# Autogenerated file; please don't edit
# date: 2024-05-13 13:33:05.137460

########################################################################
#
# Copyright 2024 IHP PDK Authors
# 
# Licensed under the Apache License, Version 2.0 (the "License");
# you may not use this file except in compliance with the License.
# You may obtain a copy of the License at
# 
#    https://www.apache.org/licenses/LICENSE-2.0
# 
# Unless required by applicable law or agreed to in writing, software
# distributed under the License is distributed on an "AS IS" BASIS,
# WITHOUT WARRANTIES OR CONDITIONS OF ANY KIND, either express or implied.
# See the License for the specific language governing permissions and
# limitations under the License.
#
########################################################################

VERSION 5.7 ;

SITE sg13g2_ioSite
    CLASS PAD ;
    SYMMETRY R90 ;
    SIZE 1.00 BY 180.00 ;
END sg13g2_ioSite

SITE sg13g2_cornerSite
    CLASS PAD ;
    SYMMETRY R90 ;
    SIZE 180.00 BY 180.00 ;
END sg13g2_cornerSite

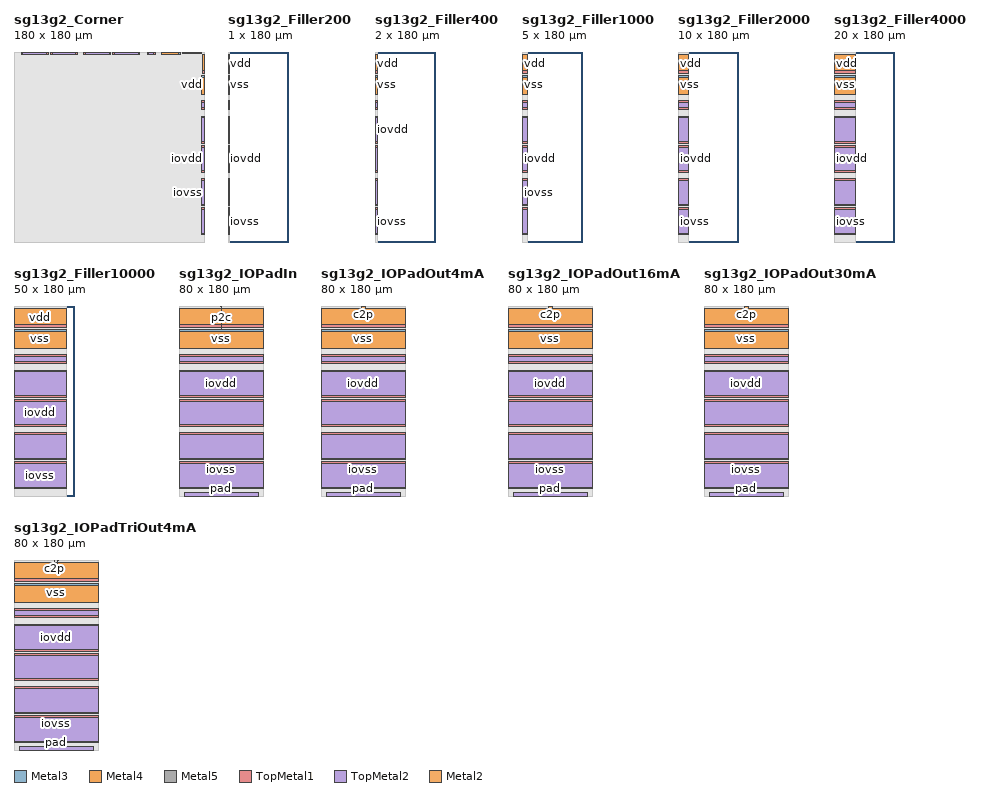
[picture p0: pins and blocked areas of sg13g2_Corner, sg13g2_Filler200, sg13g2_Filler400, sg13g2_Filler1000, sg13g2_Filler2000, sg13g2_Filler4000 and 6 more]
MACRO sg13g2_Corner
    CLASS PAD SPACER ;
    ORIGIN 0.000 0.000 ;
    FOREIGN sg13g2_Corner 0.000 0.000 ;
    SIZE 180.000 BY 180.000 ;
    SYMMETRY X Y R90 ;
    SITE sg13g2_cornerSite ;
  PIN iovdd
    DIRECTION INOUT ;
    USE POWER ;
    PORT
      LAYER Metal3 ;
        RECT 178.000 66.000 180.000 91.500 ;
    END
    PORT
      LAYER Metal3 ;
        RECT 93.500 178.000 119.000 180.000 ;
    END
    PORT
      LAYER Metal3 ;
        RECT 66.000 178.000 91.500 180.000 ;
    END
    PORT
      LAYER Metal3 ;
        RECT 178.000 93.500 180.000 119.000 ;
    END
    PORT
      LAYER Metal4 ;
        RECT 178.000 66.000 180.000 91.500 ;
    END
    PORT
      LAYER Metal4 ;
        RECT 93.500 178.000 119.000 180.000 ;
    END
    PORT
      LAYER Metal4 ;
        RECT 66.000 178.000 91.500 180.000 ;
    END
    PORT
      LAYER Metal4 ;
        RECT 178.000 93.500 180.000 119.000 ;
    END
    PORT
      LAYER Metal5 ;
        RECT 178.000 66.000 180.000 91.500 ;
    END
    PORT
      LAYER Metal5 ;
        RECT 93.500 178.000 119.000 180.000 ;
    END
    PORT
      LAYER Metal5 ;
        RECT 66.000 178.000 91.500 180.000 ;
    END
    PORT
      LAYER Metal5 ;
        RECT 178.000 93.500 180.000 119.000 ;
    END
    PORT
      LAYER TopMetal1 ;
        RECT 178.000 66.000 180.000 91.500 ;
    END
    PORT
      LAYER TopMetal1 ;
        RECT 93.500 178.000 119.000 180.000 ;
    END
    PORT
      LAYER TopMetal1 ;
        RECT 66.000 178.000 91.500 180.000 ;
    END
    PORT
      LAYER TopMetal1 ;
        RECT 178.000 93.500 180.000 119.000 ;
    END
    PORT
      LAYER TopMetal2 ;
        RECT 67.500 178.000 90.000 180.000 ;
    END
    PORT
      LAYER TopMetal2 ;
        RECT 178.000 67.500 180.000 90.000 ;
    END
    PORT
      LAYER TopMetal2 ;
        RECT 95.000 178.000 117.500 180.000 ;
    END
    PORT
      LAYER TopMetal2 ;
        RECT 178.000 95.000 180.000 117.500 ;
    END
  END iovdd
  PIN iovss
    DIRECTION INOUT ;
    USE GROUND ;
    PORT
      LAYER Metal3 ;
        RECT 178.000 34.500 180.000 60.000 ;
    END
    PORT
      LAYER Metal3 ;
        RECT 7.000 178.000 32.500 180.000 ;
    END
    PORT
      LAYER Metal3 ;
        RECT 178.000 126.000 180.000 134.000 ;
    END
    PORT
      LAYER Metal3 ;
        RECT 126.000 178.000 134.000 180.000 ;
    END
    PORT
      LAYER Metal3 ;
        RECT 34.500 178.000 60.000 180.000 ;
    END
    PORT
      LAYER Metal3 ;
        RECT 178.000 7.000 180.000 32.500 ;
    END
    PORT
      LAYER Metal4 ;
        RECT 178.000 34.500 180.000 60.000 ;
    END
    PORT
      LAYER Metal4 ;
        RECT 7.000 178.000 32.500 180.000 ;
    END
    PORT
      LAYER Metal4 ;
        RECT 178.000 126.000 180.000 134.000 ;
    END
    PORT
      LAYER Metal4 ;
        RECT 126.000 178.000 134.000 180.000 ;
    END
    PORT
      LAYER Metal4 ;
        RECT 34.500 178.000 60.000 180.000 ;
    END
    PORT
      LAYER Metal4 ;
        RECT 178.000 7.000 180.000 32.500 ;
    END
    PORT
      LAYER Metal5 ;
        RECT 178.000 34.500 180.000 60.000 ;
    END
    PORT
      LAYER Metal5 ;
        RECT 7.000 178.000 32.500 180.000 ;
    END
    PORT
      LAYER Metal5 ;
        RECT 178.000 126.000 180.000 134.000 ;
    END
    PORT
      LAYER Metal5 ;
        RECT 126.000 178.000 134.000 180.000 ;
    END
    PORT
      LAYER Metal5 ;
        RECT 34.500 178.000 60.000 180.000 ;
    END
    PORT
      LAYER Metal5 ;
        RECT 178.000 7.000 180.000 32.500 ;
    END
    PORT
      LAYER TopMetal1 ;
        RECT 178.000 34.500 180.000 60.000 ;
    END
    PORT
      LAYER TopMetal1 ;
        RECT 7.000 178.000 32.500 180.000 ;
    END
    PORT
      LAYER TopMetal1 ;
        RECT 178.000 126.000 180.000 134.000 ;
    END
    PORT
      LAYER TopMetal1 ;
        RECT 126.000 178.000 134.000 180.000 ;
    END
    PORT
      LAYER TopMetal1 ;
        RECT 34.500 178.000 60.000 180.000 ;
    END
    PORT
      LAYER TopMetal1 ;
        RECT 178.000 7.000 180.000 32.500 ;
    END
    PORT
      LAYER TopMetal2 ;
        RECT 178.000 127.500 180.000 132.500 ;
    END
    PORT
      LAYER TopMetal2 ;
        RECT 178.000 36.000 180.000 58.500 ;
    END
    PORT
      LAYER TopMetal2 ;
        RECT 8.500 178.000 31.000 180.000 ;
    END
    PORT
      LAYER TopMetal2 ;
        RECT 178.000 8.500 180.000 31.000 ;
    END
    PORT
      LAYER TopMetal2 ;
        RECT 36.000 178.000 58.500 180.000 ;
    END
    PORT
      LAYER TopMetal2 ;
        RECT 127.500 178.000 132.500 180.000 ;
    END
  END iovss
  PIN vdd
    DIRECTION INOUT ;
    USE POWER ;
    PORT
      LAYER Metal3 ;
        RECT 160.000 178.590 178.000 180.000 ;
    END
    PORT
      LAYER Metal3 ;
        RECT 178.590 160.000 180.000 178.000 ;
    END
    PORT
      LAYER Metal4 ;
        RECT 178.000 140.000 180.000 155.800 ;
    END
    PORT
      LAYER Metal4 ;
        RECT 140.000 178.000 155.800 180.000 ;
    END
    PORT
      LAYER Metal5 ;
        RECT 178.000 140.000 180.000 158.000 ;
    END
    PORT
      LAYER Metal5 ;
        RECT 140.000 178.000 158.000 180.000 ;
    END
    PORT
      LAYER TopMetal1 ;
        RECT 178.000 140.000 180.000 158.000 ;
    END
    PORT
      LAYER TopMetal1 ;
        RECT 140.000 178.000 158.000 180.000 ;
    END
  END vdd
  PIN vss
    DIRECTION INOUT ;
    USE GROUND ;
    PORT
      LAYER Metal3 ;
        RECT 178.000 140.000 180.000 158.000 ;
    END
    PORT
      LAYER Metal3 ;
        RECT 140.000 178.000 158.000 180.000 ;
    END
    PORT
      LAYER Metal4 ;
        RECT 178.590 162.200 180.000 178.000 ;
    END
    PORT
      LAYER Metal4 ;
        RECT 162.200 178.590 178.000 180.000 ;
    END
    PORT
      LAYER Metal5 ;
        RECT 160.000 178.590 178.000 180.000 ;
    END
    PORT
      LAYER Metal5 ;
        RECT 178.590 160.000 180.000 178.000 ;
    END
    PORT
      LAYER TopMetal1 ;
        RECT 160.000 178.590 178.000 180.000 ;
    END
    PORT
      LAYER TopMetal1 ;
        RECT 178.590 160.000 180.000 178.000 ;
    END
  END vss
  OBS
    LAYER Metal1 ;
      RECT 0.000 0.000 180.000 180.000 ;
    LAYER Metal2 ;
      RECT 0.000 0.000 180.000 180.000 ;
    LAYER Metal3 ;
      RECT 0.000 0.000 180.000 180.000 ;
    LAYER Metal4 ;
      RECT 0.000 0.000 180.000 180.000 ;
    LAYER Metal5 ;
      RECT 0.000 0.000 180.000 180.000 ;
    LAYER TopMetal1 ;
      RECT 0.000 0.000 180.000 180.000 ;
    LAYER TopMetal2 ;
      RECT 0.000 0.000 180.000 180.000 ;
    LAYER Via1 ;
      RECT 0.000 0.000 180.000 180.000 ;
    LAYER Via2 ;
      RECT 0.000 0.000 180.000 180.000 ;
  END
END sg13g2_Corner

MACRO sg13g2_Filler200
    CLASS PAD SPACER ;
    ORIGIN 0.000 0.000 ;
    FOREIGN sg13g2_Filler200 0.000 0.000 ;
    SIZE 1.000 BY 180.000 ;
    SYMMETRY X Y R90 ;
    SITE sg13g2_ioSite ;
  PIN iovdd
    DIRECTION INOUT ;
    USE POWER ;
    PORT
      LAYER Metal3 ;
        RECT 0.000 66.000 1.000 91.500 ;
    END
    PORT
      LAYER Metal3 ;
        RECT 0.000 93.500 1.000 119.000 ;
    END
    PORT
      LAYER Metal4 ;
        RECT 0.000 66.000 1.000 91.500 ;
    END
    PORT
      LAYER Metal4 ;
        RECT 0.000 93.500 1.000 119.000 ;
    END
    PORT
      LAYER Metal5 ;
        RECT 0.000 66.000 1.000 91.500 ;
    END
    PORT
      LAYER Metal5 ;
        RECT 0.000 93.500 1.000 119.000 ;
    END
    PORT
      LAYER TopMetal1 ;
        RECT 0.000 66.000 1.000 91.500 ;
    END
    PORT
      LAYER TopMetal1 ;
        RECT 0.000 93.500 1.000 119.000 ;
    END
    PORT
      LAYER TopMetal2 ;
        RECT 0.000 95.000 1.000 117.500 ;
    END
    PORT
      LAYER TopMetal2 ;
        RECT 0.000 67.500 1.000 90.000 ;
    END
  END iovdd
  PIN iovss
    DIRECTION INOUT ;
    USE GROUND ;
    PORT
      LAYER Metal3 ;
        RECT 0.000 7.000 1.000 32.500 ;
    END
    PORT
      LAYER Metal3 ;
        RECT 0.000 126.000 1.000 134.000 ;
    END
    PORT
      LAYER Metal3 ;
        RECT 0.000 34.500 1.000 60.000 ;
    END
    PORT
      LAYER Metal4 ;
        RECT 0.000 7.000 1.000 32.500 ;
    END
    PORT
      LAYER Metal4 ;
        RECT 0.000 126.000 1.000 134.000 ;
    END
    PORT
      LAYER Metal4 ;
        RECT 0.000 34.500 1.000 60.000 ;
    END
    PORT
      LAYER Metal5 ;
        RECT 0.000 7.000 1.000 32.500 ;
    END
    PORT
      LAYER Metal5 ;
        RECT 0.000 126.000 1.000 134.000 ;
    END
    PORT
      LAYER Metal5 ;
        RECT 0.000 34.500 1.000 60.000 ;
    END
    PORT
      LAYER TopMetal1 ;
        RECT 0.000 7.000 1.000 32.500 ;
    END
    PORT
      LAYER TopMetal1 ;
        RECT 0.000 126.000 1.000 134.000 ;
    END
    PORT
      LAYER TopMetal1 ;
        RECT 0.000 34.500 1.000 60.000 ;
    END
    PORT
      LAYER TopMetal2 ;
        RECT 0.000 8.500 1.000 31.000 ;
    END
    PORT
      LAYER TopMetal2 ;
        RECT 0.000 127.500 1.000 132.500 ;
    END
    PORT
      LAYER TopMetal2 ;
        RECT 0.000 36.000 1.000 58.500 ;
    END
  END iovss
  PIN vdd
    DIRECTION INOUT ;
    USE POWER ;
    PORT
      LAYER Metal3 ;
        RECT 0.000 160.000 1.000 178.000 ;
    END
    PORT
      LAYER Metal4 ;
        RECT 0.000 140.000 1.000 155.800 ;
    END
    PORT
      LAYER Metal5 ;
        RECT 0.000 140.000 1.000 158.000 ;
    END
    PORT
      LAYER TopMetal1 ;
        RECT 0.000 140.000 1.000 158.000 ;
    END
  END vdd
  PIN vss
    DIRECTION INOUT ;
    USE GROUND ;
    PORT
      LAYER Metal3 ;
        RECT 0.000 140.000 1.000 158.000 ;
    END
    PORT
      LAYER Metal4 ;
        RECT 0.000 162.200 1.000 178.000 ;
    END
    PORT
      LAYER Metal5 ;
        RECT 0.000 160.000 1.000 178.000 ;
    END
    PORT
      LAYER TopMetal1 ;
        RECT 0.000 160.000 1.000 178.000 ;
    END
  END vss
  OBS
    LAYER Metal1 ;
      RECT 0.000 0.000 1.000 180.000 ;
    LAYER Metal2 ;
      RECT 0.000 0.000 1.000 180.000 ;
    LAYER Metal3 ;
      RECT 0.000 0.000 1.000 178.000 ;
    LAYER Metal4 ;
      RECT 0.000 0.000 1.000 178.000 ;
    LAYER Metal5 ;
      RECT 0.000 0.000 1.000 178.000 ;
    LAYER TopMetal1 ;
      RECT 0.000 0.000 1.000 178.000 ;
    LAYER TopMetal2 ;
      RECT 0.000 8.500 1.000 132.500 ;
    LAYER Via1 ;
      RECT 0.000 0.000 1.000 180.000 ;
    LAYER Via2 ;
      RECT 0.000 0.000 1.000 180.000 ;
  END
END sg13g2_Filler200

MACRO sg13g2_Filler400
    CLASS PAD SPACER ;
    ORIGIN 0.000 0.000 ;
    FOREIGN sg13g2_Filler400 0.000 0.000 ;
    SIZE 2.000 BY 180.000 ;
    SYMMETRY X Y R90 ;
    SITE sg13g2_ioSite ;
  PIN iovdd
    DIRECTION INOUT ;
    USE POWER ;
    PORT
      LAYER Metal3 ;
        RECT 0.000 93.500 2.000 119.000 ;
    END
    PORT
      LAYER Metal3 ;
        RECT 0.000 66.000 2.000 91.500 ;
    END
    PORT
      LAYER Metal4 ;
        RECT 0.000 93.500 2.000 119.000 ;
    END
    PORT
      LAYER Metal4 ;
        RECT 0.000 66.000 2.000 91.500 ;
    END
    PORT
      LAYER Metal5 ;
        RECT 0.000 93.500 2.000 119.000 ;
    END
    PORT
      LAYER Metal5 ;
        RECT 0.000 66.000 2.000 91.500 ;
    END
    PORT
      LAYER TopMetal1 ;
        RECT 0.000 93.500 2.000 119.000 ;
    END
    PORT
      LAYER TopMetal1 ;
        RECT 0.000 66.000 2.000 91.500 ;
    END
    PORT
      LAYER TopMetal2 ;
        RECT 0.000 67.500 2.000 90.000 ;
    END
    PORT
      LAYER TopMetal2 ;
        RECT 0.000 95.000 2.000 117.500 ;
    END
  END iovdd
  PIN iovss
    DIRECTION INOUT ;
    USE GROUND ;
    PORT
      LAYER Metal3 ;
        RECT 0.000 126.000 2.000 134.000 ;
    END
    PORT
      LAYER Metal3 ;
        RECT 0.000 7.000 2.000 32.500 ;
    END
    PORT
      LAYER Metal3 ;
        RECT 0.000 34.500 2.000 60.000 ;
    END
    PORT
      LAYER Metal4 ;
        RECT 0.000 126.000 2.000 134.000 ;
    END
    PORT
      LAYER Metal4 ;
        RECT 0.000 7.000 2.000 32.500 ;
    END
    PORT
      LAYER Metal4 ;
        RECT 0.000 34.500 2.000 60.000 ;
    END
    PORT
      LAYER Metal5 ;
        RECT 0.000 126.000 2.000 134.000 ;
    END
    PORT
      LAYER Metal5 ;
        RECT 0.000 7.000 2.000 32.500 ;
    END
    PORT
      LAYER Metal5 ;
        RECT 0.000 34.500 2.000 60.000 ;
    END
    PORT
      LAYER TopMetal1 ;
        RECT 0.000 126.000 2.000 134.000 ;
    END
    PORT
      LAYER TopMetal1 ;
        RECT 0.000 7.000 2.000 32.500 ;
    END
    PORT
      LAYER TopMetal1 ;
        RECT 0.000 34.500 2.000 60.000 ;
    END
    PORT
      LAYER TopMetal2 ;
        RECT 0.000 8.500 2.000 31.000 ;
    END
    PORT
      LAYER TopMetal2 ;
        RECT 0.000 36.000 2.000 58.500 ;
    END
    PORT
      LAYER TopMetal2 ;
        RECT 0.000 127.500 2.000 132.500 ;
    END
  END iovss
  PIN vdd
    DIRECTION INOUT ;
    USE POWER ;
    PORT
      LAYER Metal3 ;
        RECT 0.000 160.000 2.000 178.000 ;
    END
    PORT
      LAYER Metal4 ;
        RECT 0.000 140.000 2.000 155.800 ;
    END
    PORT
      LAYER Metal5 ;
        RECT 0.000 140.000 2.000 158.000 ;
    END
    PORT
      LAYER TopMetal1 ;
        RECT 0.000 140.000 2.000 158.000 ;
    END
  END vdd
  PIN vss
    DIRECTION INOUT ;
    USE GROUND ;
    PORT
      LAYER Metal3 ;
        RECT 0.000 140.000 2.000 158.000 ;
    END
    PORT
      LAYER Metal4 ;
        RECT 0.000 162.200 2.000 178.000 ;
    END
    PORT
      LAYER Metal5 ;
        RECT 0.000 160.000 2.000 178.000 ;
    END
    PORT
      LAYER TopMetal1 ;
        RECT 0.000 160.000 2.000 178.000 ;
    END
  END vss
  OBS
    LAYER Metal1 ;
      RECT 0.000 0.000 2.000 180.000 ;
    LAYER Metal2 ;
      RECT 0.000 0.000 2.000 180.000 ;
    LAYER Metal3 ;
      RECT 0.000 0.000 2.000 178.000 ;
    LAYER Metal4 ;
      RECT 0.000 0.000 2.000 178.000 ;
    LAYER Metal5 ;
      RECT 0.000 0.000 2.000 178.000 ;
    LAYER TopMetal1 ;
      RECT 0.000 0.000 2.000 178.000 ;
    LAYER TopMetal2 ;
      RECT 0.000 8.500 2.000 132.500 ;
    LAYER Via1 ;
      RECT 0.000 0.000 2.000 180.000 ;
    LAYER Via2 ;
      RECT 0.000 0.000 2.000 180.000 ;
  END
END sg13g2_Filler400

MACRO sg13g2_Filler1000
    CLASS PAD SPACER ;
    ORIGIN 0.000 0.000 ;
    FOREIGN sg13g2_Filler1000 0.000 0.000 ;
    SIZE 5.000 BY 180.000 ;
    SYMMETRY X Y R90 ;
    SITE sg13g2_ioSite ;
  PIN iovdd
    DIRECTION INOUT ;
    USE POWER ;
    PORT
      LAYER Metal3 ;
        RECT 0.000 66.000 5.000 91.500 ;
    END
    PORT
      LAYER Metal3 ;
        RECT 0.000 93.500 5.000 119.000 ;
    END
    PORT
      LAYER Metal4 ;
        RECT 0.000 66.000 5.000 91.500 ;
    END
    PORT
      LAYER Metal4 ;
        RECT 0.000 93.500 5.000 119.000 ;
    END
    PORT
      LAYER Metal5 ;
        RECT 0.000 66.000 5.000 91.500 ;
    END
    PORT
      LAYER Metal5 ;
        RECT 0.000 93.500 5.000 119.000 ;
    END
    PORT
      LAYER TopMetal1 ;
        RECT 0.000 66.000 5.000 91.500 ;
    END
    PORT
      LAYER TopMetal1 ;
        RECT 0.000 93.500 5.000 119.000 ;
    END
    PORT
      LAYER TopMetal2 ;
        RECT 0.000 95.000 5.000 117.500 ;
    END
    PORT
      LAYER TopMetal2 ;
        RECT 0.000 67.500 5.000 90.000 ;
    END
  END iovdd
  PIN iovss
    DIRECTION INOUT ;
    USE GROUND ;
    PORT
      LAYER Metal3 ;
        RECT 0.000 34.500 5.000 60.000 ;
    END
    PORT
      LAYER Metal3 ;
        RECT 0.000 7.000 5.000 32.500 ;
    END
    PORT
      LAYER Metal3 ;
        RECT 0.000 126.000 5.000 134.000 ;
    END
    PORT
      LAYER Metal4 ;
        RECT 0.000 34.500 5.000 60.000 ;
    END
    PORT
      LAYER Metal4 ;
        RECT 0.000 7.000 5.000 32.500 ;
    END
    PORT
      LAYER Metal4 ;
        RECT 0.000 126.000 5.000 134.000 ;
    END
    PORT
      LAYER Metal5 ;
        RECT 0.000 34.500 5.000 60.000 ;
    END
    PORT
      LAYER Metal5 ;
        RECT 0.000 7.000 5.000 32.500 ;
    END
    PORT
      LAYER Metal5 ;
        RECT 0.000 126.000 5.000 134.000 ;
    END
    PORT
      LAYER TopMetal1 ;
        RECT 0.000 34.500 5.000 60.000 ;
    END
    PORT
      LAYER TopMetal1 ;
        RECT 0.000 7.000 5.000 32.500 ;
    END
    PORT
      LAYER TopMetal1 ;
        RECT 0.000 126.000 5.000 134.000 ;
    END
    PORT
      LAYER TopMetal2 ;
        RECT 0.000 127.500 5.000 132.500 ;
    END
    PORT
      LAYER TopMetal2 ;
        RECT 0.000 36.000 5.000 58.500 ;
    END
    PORT
      LAYER TopMetal2 ;
        RECT 0.000 8.500 5.000 31.000 ;
    END
  END iovss
  PIN vdd
    DIRECTION INOUT ;
    USE POWER ;
    PORT
      LAYER Metal3 ;
        RECT 0.000 160.000 5.000 178.000 ;
    END
    PORT
      LAYER Metal4 ;
        RECT 0.000 140.000 5.000 155.800 ;
    END
    PORT
      LAYER Metal5 ;
        RECT 0.000 140.000 5.000 158.000 ;
    END
    PORT
      LAYER TopMetal1 ;
        RECT 0.000 140.000 5.000 158.000 ;
    END
  END vdd
  PIN vss
    DIRECTION INOUT ;
    USE GROUND ;
    PORT
      LAYER Metal3 ;
        RECT 0.000 140.000 5.000 158.000 ;
    END
    PORT
      LAYER Metal4 ;
        RECT 0.000 162.200 5.000 178.000 ;
    END
    PORT
      LAYER Metal5 ;
        RECT 0.000 160.000 5.000 178.000 ;
    END
    PORT
      LAYER TopMetal1 ;
        RECT 0.000 160.000 5.000 178.000 ;
    END
  END vss
  OBS
    LAYER Metal1 ;
      RECT 0.000 0.000 5.000 180.000 ;
    LAYER Metal2 ;
      RECT 0.000 0.000 5.000 180.000 ;
    LAYER Metal3 ;
      RECT 0.000 0.000 5.000 178.000 ;
    LAYER Metal4 ;
      RECT 0.000 0.000 5.000 178.000 ;
    LAYER Metal5 ;
      RECT 0.000 0.000 5.000 178.000 ;
    LAYER TopMetal1 ;
      RECT 0.000 0.000 5.000 178.000 ;
    LAYER TopMetal2 ;
      RECT 0.000 8.500 5.000 132.500 ;
    LAYER Via1 ;
      RECT 0.000 0.000 5.000 180.000 ;
    LAYER Via2 ;
      RECT 0.000 0.000 5.000 180.000 ;
  END
END sg13g2_Filler1000

MACRO sg13g2_Filler2000
    CLASS PAD SPACER ;
    ORIGIN 0.000 0.000 ;
    FOREIGN sg13g2_Filler2000 0.000 0.000 ;
    SIZE 10.000 BY 180.000 ;
    SYMMETRY X Y R90 ;
    SITE sg13g2_ioSite ;
  PIN iovdd
    DIRECTION INOUT ;
    USE POWER ;
    PORT
      LAYER Metal3 ;
        RECT 0.000 66.000 10.000 91.500 ;
    END
    PORT
      LAYER Metal3 ;
        RECT 0.000 93.500 10.000 119.000 ;
    END
    PORT
      LAYER Metal4 ;
        RECT 0.000 66.000 10.000 91.500 ;
    END
    PORT
      LAYER Metal4 ;
        RECT 0.000 93.500 10.000 119.000 ;
    END
    PORT
      LAYER Metal5 ;
        RECT 0.000 66.000 10.000 91.500 ;
    END
    PORT
      LAYER Metal5 ;
        RECT 0.000 93.500 10.000 119.000 ;
    END
    PORT
      LAYER TopMetal1 ;
        RECT 0.000 66.000 10.000 91.500 ;
    END
    PORT
      LAYER TopMetal1 ;
        RECT 0.000 93.500 10.000 119.000 ;
    END
    PORT
      LAYER TopMetal2 ;
        RECT 0.000 67.500 10.000 90.000 ;
    END
    PORT
      LAYER TopMetal2 ;
        RECT 0.000 95.000 10.000 117.500 ;
    END
  END iovdd
  PIN iovss
    DIRECTION INOUT ;
    USE GROUND ;
    PORT
      LAYER Metal3 ;
        RECT 0.000 126.000 10.000 134.000 ;
    END
    PORT
      LAYER Metal3 ;
        RECT 0.000 7.000 10.000 32.500 ;
    END
    PORT
      LAYER Metal3 ;
        RECT 0.000 34.500 10.000 60.000 ;
    END
    PORT
      LAYER Metal4 ;
        RECT 0.000 126.000 10.000 134.000 ;
    END
    PORT
      LAYER Metal4 ;
        RECT 0.000 7.000 10.000 32.500 ;
    END
    PORT
      LAYER Metal4 ;
        RECT 0.000 34.500 10.000 60.000 ;
    END
    PORT
      LAYER Metal5 ;
        RECT 0.000 126.000 10.000 134.000 ;
    END
    PORT
      LAYER Metal5 ;
        RECT 0.000 7.000 10.000 32.500 ;
    END
    PORT
      LAYER Metal5 ;
        RECT 0.000 34.500 10.000 60.000 ;
    END
    PORT
      LAYER TopMetal1 ;
        RECT 0.000 126.000 10.000 134.000 ;
    END
    PORT
      LAYER TopMetal1 ;
        RECT 0.000 7.000 10.000 32.500 ;
    END
    PORT
      LAYER TopMetal1 ;
        RECT 0.000 34.500 10.000 60.000 ;
    END
    PORT
      LAYER TopMetal2 ;
        RECT 0.000 8.500 10.000 31.000 ;
    END
    PORT
      LAYER TopMetal2 ;
        RECT 0.000 36.000 10.000 58.500 ;
    END
    PORT
      LAYER TopMetal2 ;
        RECT 0.000 127.500 10.000 132.500 ;
    END
  END iovss
  PIN vdd
    DIRECTION INOUT ;
    USE POWER ;
    PORT
      LAYER Metal3 ;
        RECT 0.000 160.000 10.000 178.000 ;
    END
    PORT
      LAYER Metal4 ;
        RECT 0.000 140.000 10.000 155.800 ;
    END
    PORT
      LAYER Metal5 ;
        RECT 0.000 140.000 10.000 158.000 ;
    END
    PORT
      LAYER TopMetal1 ;
        RECT 0.000 140.000 10.000 158.000 ;
    END
  END vdd
  PIN vss
    DIRECTION INOUT ;
    USE GROUND ;
    PORT
      LAYER Metal3 ;
        RECT 0.000 140.000 10.000 158.000 ;
    END
    PORT
      LAYER Metal4 ;
        RECT 0.000 162.200 10.000 178.000 ;
    END
    PORT
      LAYER Metal5 ;
        RECT 0.000 160.000 10.000 178.000 ;
    END
    PORT
      LAYER TopMetal1 ;
        RECT 0.000 160.000 10.000 178.000 ;
    END
  END vss
  OBS
    LAYER Metal1 ;
      RECT 0.000 0.000 10.000 180.000 ;
    LAYER Metal2 ;
      RECT 0.000 0.000 10.000 180.000 ;
    LAYER Metal3 ;
      RECT 0.000 0.000 10.000 178.000 ;
    LAYER Metal4 ;
      RECT 0.000 0.000 10.000 178.000 ;
    LAYER Metal5 ;
      RECT 0.000 0.000 10.000 178.000 ;
    LAYER TopMetal1 ;
      RECT 0.000 0.000 10.000 178.000 ;
    LAYER TopMetal2 ;
      RECT 0.000 8.500 10.000 132.500 ;
    LAYER Via1 ;
      RECT 0.000 0.000 10.000 180.000 ;
    LAYER Via2 ;
      RECT 0.000 0.000 10.000 180.000 ;
  END
END sg13g2_Filler2000

MACRO sg13g2_Filler4000
    CLASS PAD SPACER ;
    ORIGIN 0.000 0.000 ;
    FOREIGN sg13g2_Filler4000 0.000 0.000 ;
    SIZE 20.000 BY 180.000 ;
    SYMMETRY X Y R90 ;
    SITE sg13g2_ioSite ;
  PIN iovdd
    DIRECTION INOUT ;
    USE POWER ;
    PORT
      LAYER Metal3 ;
        RECT 0.000 66.000 20.000 91.500 ;
    END
    PORT
      LAYER Metal3 ;
        RECT 0.000 93.500 20.000 119.000 ;
    END
    PORT
      LAYER Metal4 ;
        RECT 0.000 66.000 20.000 91.500 ;
    END
    PORT
      LAYER Metal4 ;
        RECT 0.000 93.500 20.000 119.000 ;
    END
    PORT
      LAYER Metal5 ;
        RECT 0.000 66.000 20.000 91.500 ;
    END
    PORT
      LAYER Metal5 ;
        RECT 0.000 93.500 20.000 119.000 ;
    END
    PORT
      LAYER TopMetal1 ;
        RECT 0.000 66.000 20.000 91.500 ;
    END
    PORT
      LAYER TopMetal1 ;
        RECT 0.000 93.500 20.000 119.000 ;
    END
    PORT
      LAYER TopMetal2 ;
        RECT 0.000 95.000 20.000 117.500 ;
    END
    PORT
      LAYER TopMetal2 ;
        RECT 0.000 67.500 20.000 90.000 ;
    END
  END iovdd
  PIN iovss
    DIRECTION INOUT ;
    USE GROUND ;
    PORT
      LAYER Metal3 ;
        RECT 0.000 7.000 20.000 32.500 ;
    END
    PORT
      LAYER Metal3 ;
        RECT 0.000 34.500 20.000 60.000 ;
    END
    PORT
      LAYER Metal3 ;
        RECT 0.000 126.000 20.000 134.000 ;
    END
    PORT
      LAYER Metal4 ;
        RECT 0.000 7.000 20.000 32.500 ;
    END
    PORT
      LAYER Metal4 ;
        RECT 0.000 34.500 20.000 60.000 ;
    END
    PORT
      LAYER Metal4 ;
        RECT 0.000 126.000 20.000 134.000 ;
    END
    PORT
      LAYER Metal5 ;
        RECT 0.000 7.000 20.000 32.500 ;
    END
    PORT
      LAYER Metal5 ;
        RECT 0.000 34.500 20.000 60.000 ;
    END
    PORT
      LAYER Metal5 ;
        RECT 0.000 126.000 20.000 134.000 ;
    END
    PORT
      LAYER TopMetal1 ;
        RECT 0.000 7.000 20.000 32.500 ;
    END
    PORT
      LAYER TopMetal1 ;
        RECT 0.000 34.500 20.000 60.000 ;
    END
    PORT
      LAYER TopMetal1 ;
        RECT 0.000 126.000 20.000 134.000 ;
    END
    PORT
      LAYER TopMetal2 ;
        RECT 0.000 127.500 20.000 132.500 ;
    END
    PORT
      LAYER TopMetal2 ;
        RECT 0.000 36.000 20.000 58.500 ;
    END
    PORT
      LAYER TopMetal2 ;
        RECT 0.000 8.500 20.000 31.000 ;
    END
  END iovss
  PIN vdd
    DIRECTION INOUT ;
    USE POWER ;
    PORT
      LAYER Metal3 ;
        RECT 0.000 160.000 20.000 178.000 ;
    END
    PORT
      LAYER Metal4 ;
        RECT 0.000 140.000 20.000 155.800 ;
    END
    PORT
      LAYER Metal5 ;
        RECT 0.000 140.000 20.000 158.000 ;
    END
    PORT
      LAYER TopMetal1 ;
        RECT 0.000 140.000 20.000 158.000 ;
    END
  END vdd
  PIN vss
    DIRECTION INOUT ;
    USE GROUND ;
    PORT
      LAYER Metal3 ;
        RECT 0.000 140.000 20.000 158.000 ;
    END
    PORT
      LAYER Metal4 ;
        RECT 0.000 162.200 20.000 178.000 ;
    END
    PORT
      LAYER Metal5 ;
        RECT 0.000 160.000 20.000 178.000 ;
    END
    PORT
      LAYER TopMetal1 ;
        RECT 0.000 160.000 20.000 178.000 ;
    END
  END vss
  OBS
    LAYER Metal1 ;
      RECT 0.000 0.000 20.000 180.000 ;
    LAYER Metal2 ;
      RECT 0.000 0.000 20.000 180.000 ;
    LAYER Metal3 ;
      RECT 0.000 0.000 20.000 178.000 ;
    LAYER Metal4 ;
      RECT 0.000 0.000 20.000 178.000 ;
    LAYER Metal5 ;
      RECT 0.000 0.000 20.000 178.000 ;
    LAYER TopMetal1 ;
      RECT 0.000 0.000 20.000 178.000 ;
    LAYER TopMetal2 ;
      RECT 0.000 8.500 20.000 132.500 ;
    LAYER Via1 ;
      RECT 0.000 0.000 20.000 180.000 ;
    LAYER Via2 ;
      RECT 0.000 0.000 20.000 180.000 ;
  END
END sg13g2_Filler4000

MACRO sg13g2_Filler10000
    CLASS PAD SPACER ;
    ORIGIN 0.000 0.000 ;
    FOREIGN sg13g2_Filler10000 0.000 0.000 ;
    SIZE 50.000 BY 180.000 ;
    SYMMETRY X Y R90 ;
    SITE sg13g2_ioSite ;
  PIN iovdd
    DIRECTION INOUT ;
    USE POWER ;
    PORT
      LAYER Metal3 ;
        RECT 0.000 66.000 50.000 91.500 ;
    END
    PORT
      LAYER Metal3 ;
        RECT 0.000 93.500 50.000 119.000 ;
    END
    PORT
      LAYER Metal4 ;
        RECT 0.000 66.000 50.000 91.500 ;
    END
    PORT
      LAYER Metal4 ;
        RECT 0.000 93.500 50.000 119.000 ;
    END
    PORT
      LAYER Metal5 ;
        RECT 0.000 66.000 50.000 91.500 ;
    END
    PORT
      LAYER Metal5 ;
        RECT 0.000 93.500 50.000 119.000 ;
    END
    PORT
      LAYER TopMetal1 ;
        RECT 0.000 66.000 50.000 91.500 ;
    END
    PORT
      LAYER TopMetal1 ;
        RECT 0.000 93.500 50.000 119.000 ;
    END
    PORT
      LAYER TopMetal2 ;
        RECT 0.000 95.000 50.000 117.500 ;
    END
    PORT
      LAYER TopMetal2 ;
        RECT 0.000 67.500 50.000 90.000 ;
    END
  END iovdd
  PIN iovss
    DIRECTION INOUT ;
    USE GROUND ;
    PORT
      LAYER Metal3 ;
        RECT 0.000 7.000 50.000 32.500 ;
    END
    PORT
      LAYER Metal3 ;
        RECT 0.000 126.000 50.000 134.000 ;
    END
    PORT
      LAYER Metal3 ;
        RECT 0.000 34.500 50.000 60.000 ;
    END
    PORT
      LAYER Metal4 ;
        RECT 0.000 7.000 50.000 32.500 ;
    END
    PORT
      LAYER Metal4 ;
        RECT 0.000 126.000 50.000 134.000 ;
    END
    PORT
      LAYER Metal4 ;
        RECT 0.000 34.500 50.000 60.000 ;
    END
    PORT
      LAYER Metal5 ;
        RECT 0.000 7.000 50.000 32.500 ;
    END
    PORT
      LAYER Metal5 ;
        RECT 0.000 126.000 50.000 134.000 ;
    END
    PORT
      LAYER Metal5 ;
        RECT 0.000 34.500 50.000 60.000 ;
    END
    PORT
      LAYER TopMetal1 ;
        RECT 0.000 7.000 50.000 32.500 ;
    END
    PORT
      LAYER TopMetal1 ;
        RECT 0.000 126.000 50.000 134.000 ;
    END
    PORT
      LAYER TopMetal1 ;
        RECT 0.000 34.500 50.000 60.000 ;
    END
    PORT
      LAYER TopMetal2 ;
        RECT 0.000 8.500 50.000 31.000 ;
    END
    PORT
      LAYER TopMetal2 ;
        RECT 0.000 127.500 50.000 132.500 ;
    END
    PORT
      LAYER TopMetal2 ;
        RECT 0.000 36.000 50.000 58.500 ;
    END
  END iovss
  PIN vdd
    DIRECTION INOUT ;
    USE POWER ;
    PORT
      LAYER Metal3 ;
        RECT 0.000 160.000 50.000 178.000 ;
    END
    PORT
      LAYER Metal4 ;
        RECT 0.000 140.000 50.000 155.800 ;
    END
    PORT
      LAYER Metal5 ;
        RECT 0.000 140.000 50.000 158.000 ;
    END
    PORT
      LAYER TopMetal1 ;
        RECT 0.000 140.000 50.000 158.000 ;
    END
  END vdd
  PIN vss
    DIRECTION INOUT ;
    USE GROUND ;
    PORT
      LAYER Metal3 ;
        RECT 0.000 140.000 50.000 158.000 ;
    END
    PORT
      LAYER Metal4 ;
        RECT 0.000 162.200 50.000 178.000 ;
    END
    PORT
      LAYER Metal5 ;
        RECT 0.000 160.000 50.000 178.000 ;
    END
    PORT
      LAYER TopMetal1 ;
        RECT 0.000 160.000 50.000 178.000 ;
    END
  END vss
  OBS
    LAYER Metal1 ;
      RECT 0.000 0.000 50.000 180.000 ;
    LAYER Metal2 ;
      RECT 0.000 0.000 50.000 180.000 ;
    LAYER Metal3 ;
      RECT 0.000 0.000 50.000 178.000 ;
    LAYER Metal4 ;
      RECT 0.000 0.000 50.000 178.000 ;
    LAYER Metal5 ;
      RECT 0.000 0.000 50.000 178.000 ;
    LAYER TopMetal1 ;
      RECT 0.000 0.000 50.000 178.000 ;
    LAYER TopMetal2 ;
      RECT 0.000 8.500 50.000 132.500 ;
    LAYER Via1 ;
      RECT 0.000 0.000 50.000 180.000 ;
    LAYER Via2 ;
      RECT 0.000 0.000 50.000 180.000 ;
  END
END sg13g2_Filler10000

MACRO sg13g2_IOPadIn
    CLASS PAD INPUT ;
    ORIGIN 0.000 0.000 ;
    FOREIGN sg13g2_IOPadIn 0.000 0.000 ;
    SIZE 80.000 BY 180.000 ;
    SYMMETRY X Y R90 ;
    SITE sg13g2_ioSite ;
  PIN iovdd
    DIRECTION INOUT ;
    USE POWER ;
    PORT
      LAYER Metal3 ;
        RECT 0.000 93.500 80.000 119.000 ;
    END
    PORT
      LAYER Metal3 ;
        RECT 0.000 66.000 80.000 91.500 ;
    END
    PORT
      LAYER Metal4 ;
        RECT 0.000 93.500 80.000 119.000 ;
    END
    PORT
      LAYER Metal4 ;
        RECT 0.000 66.000 80.000 91.500 ;
    END
    PORT
      LAYER Metal5 ;
        RECT 0.000 93.500 80.000 119.000 ;
    END
    PORT
      LAYER Metal5 ;
        RECT 0.000 66.000 80.000 91.500 ;
    END
    PORT
      LAYER TopMetal1 ;
        RECT 0.000 93.500 80.000 119.000 ;
    END
    PORT
      LAYER TopMetal1 ;
        RECT 0.000 66.000 80.000 91.500 ;
    END
    PORT
      LAYER TopMetal2 ;
        RECT 0.000 95.000 80.000 117.500 ;
    END
    PORT
      LAYER TopMetal2 ;
        RECT 0.000 67.500 80.000 90.000 ;
    END
  END iovdd
  PIN iovss
    DIRECTION INOUT ;
    USE GROUND ;
    PORT
      LAYER Metal3 ;
        RECT 0.000 7.000 80.000 32.500 ;
    END
    PORT
      LAYER Metal3 ;
        RECT 0.000 126.000 80.000 134.000 ;
    END
    PORT
      LAYER Metal3 ;
        RECT 0.000 34.500 80.000 60.000 ;
    END
    PORT
      LAYER Metal4 ;
        RECT 0.000 7.000 80.000 32.500 ;
    END
    PORT
      LAYER Metal4 ;
        RECT 0.000 126.000 80.000 134.000 ;
    END
    PORT
      LAYER Metal4 ;
        RECT 0.000 34.500 80.000 60.000 ;
    END
    PORT
      LAYER Metal5 ;
        RECT 0.000 7.000 80.000 32.500 ;
    END
    PORT
      LAYER Metal5 ;
        RECT 0.000 126.000 80.000 134.000 ;
    END
    PORT
      LAYER Metal5 ;
        RECT 0.000 34.500 80.000 60.000 ;
    END
    PORT
      LAYER TopMetal1 ;
        RECT 0.000 7.000 80.000 32.500 ;
    END
    PORT
      LAYER TopMetal1 ;
        RECT 0.000 126.000 80.000 134.000 ;
    END
    PORT
      LAYER TopMetal1 ;
        RECT 0.000 34.500 80.000 60.000 ;
    END
    PORT
      LAYER TopMetal2 ;
        RECT 0.000 36.000 80.000 58.500 ;
    END
    PORT
      LAYER TopMetal2 ;
        RECT 0.000 8.500 80.000 31.000 ;
    END
    PORT
      LAYER TopMetal2 ;
        RECT 0.000 127.500 80.000 132.500 ;
    END
  END iovss
  PIN p2c
    DIRECTION OUTPUT ;
    USE SIGNAL ;
    PORT
      LAYER Metal2 ;
        RECT 39.830 157.810 40.120 180.000 ;
      LAYER Metal3 ;
        RECT 39.725 179.710 40.225 180.000 ;
    END
  END p2c
  PIN pad
    DIRECTION INOUT ;
    USE SIGNAL ;
    PORT
      LAYER Metal2 ;
        RECT 5.000 0.000 75.000 3.000 ;
      LAYER Metal3 ;
        RECT 5.000 0.000 75.000 3.000 ;
      LAYER Metal4 ;
        RECT 5.000 0.000 75.000 3.000 ;
      LAYER Metal5 ;
        RECT 5.000 0.000 75.000 3.000 ;
      LAYER TopMetal1 ;
        RECT 5.000 0.000 75.000 3.000 ;
      LAYER TopMetal2 ;
        RECT 5.000 0.000 75.000 3.000 ;
    END
  END pad
  PIN vdd
    DIRECTION INOUT ;
    USE POWER ;
    PORT
      LAYER Metal3 ;
        RECT 0.000 160.000 80.000 178.000 ;
    END
    PORT
      LAYER Metal4 ;
        RECT 0.000 140.000 80.000 155.800 ;
    END
    PORT
      LAYER Metal5 ;
        RECT 0.000 140.000 80.000 158.000 ;
    END
    PORT
      LAYER TopMetal1 ;
        RECT 0.000 140.000 80.000 158.000 ;
    END
  END vdd
  PIN vss
    DIRECTION INOUT ;
    USE GROUND ;
    PORT
      LAYER Metal3 ;
        RECT 0.000 140.000 80.000 158.000 ;
    END
    PORT
      LAYER Metal4 ;
        RECT 0.000 162.200 80.000 178.000 ;
    END
    PORT
      LAYER Metal5 ;
        RECT 0.000 160.000 80.000 178.000 ;
    END
    PORT
      LAYER TopMetal1 ;
        RECT 0.000 160.000 80.000 178.000 ;
    END
  END vss
  OBS
    LAYER Metal1 ;
      RECT 0.000 0.000 80.000 180.000 ;
    LAYER Metal2 ;
      RECT 0.000 0.000 80.000 180.000 ;
    LAYER Metal3 ;
      RECT 0.000 0.000 80.000 178.000 ;
    LAYER Metal4 ;
      RECT 0.000 0.000 80.000 178.000 ;
    LAYER Metal5 ;
      RECT 0.000 0.000 80.000 178.000 ;
    LAYER TopMetal1 ;
      RECT 0.000 0.000 80.000 178.000 ;
    LAYER TopMetal2 ;
      RECT 0.000 0.000 80.000 132.500 ;
    LAYER Via1 ;
      RECT 0.000 0.000 80.000 180.000 ;
    LAYER Via2 ;
      RECT 0.000 0.000 80.000 180.000 ;
  END
END sg13g2_IOPadIn

MACRO sg13g2_IOPadOut4mA
    CLASS PAD OUTPUT ;
    ORIGIN 0.000 0.000 ;
    FOREIGN sg13g2_IOPadOut4mA 0.000 0.000 ;
    SIZE 80.000 BY 180.000 ;
    SYMMETRY X Y R90 ;
    SITE sg13g2_ioSite ;
  PIN c2p
    DIRECTION INPUT ;
    USE SIGNAL ;
    PORT
      LAYER Metal2 ;
        RECT 38.145 167.000 41.855 180.000 ;
      LAYER Metal3 ;
        RECT 38.145 179.710 41.855 180.000 ;
    END
  END c2p
  PIN iovdd
    DIRECTION INOUT ;
    USE POWER ;
    PORT
      LAYER Metal3 ;
        RECT 0.000 93.500 80.000 119.000 ;
    END
    PORT
      LAYER Metal3 ;
        RECT 0.000 66.000 80.000 91.500 ;
    END
    PORT
      LAYER Metal4 ;
        RECT 0.000 93.500 80.000 119.000 ;
    END
    PORT
      LAYER Metal4 ;
        RECT 0.000 66.000 80.000 91.500 ;
    END
    PORT
      LAYER Metal5 ;
        RECT 0.000 93.500 80.000 119.000 ;
    END
    PORT
      LAYER Metal5 ;
        RECT 0.000 66.000 80.000 91.500 ;
    END
    PORT
      LAYER TopMetal1 ;
        RECT 0.000 93.500 80.000 119.000 ;
    END
    PORT
      LAYER TopMetal1 ;
        RECT 0.000 66.000 80.000 91.500 ;
    END
    PORT
      LAYER TopMetal2 ;
        RECT 0.000 95.000 80.000 117.500 ;
    END
    PORT
      LAYER TopMetal2 ;
        RECT 0.000 67.500 80.000 90.000 ;
    END
  END iovdd
  PIN iovss
    DIRECTION INOUT ;
    USE GROUND ;
    PORT
      LAYER Metal3 ;
        RECT 0.000 7.000 80.000 32.500 ;
    END
    PORT
      LAYER Metal3 ;
        RECT 0.000 126.000 80.000 134.000 ;
    END
    PORT
      LAYER Metal3 ;
        RECT 0.000 34.500 80.000 60.000 ;
    END
    PORT
      LAYER Metal4 ;
        RECT 0.000 7.000 80.000 32.500 ;
    END
    PORT
      LAYER Metal4 ;
        RECT 0.000 126.000 80.000 134.000 ;
    END
    PORT
      LAYER Metal4 ;
        RECT 0.000 34.500 80.000 60.000 ;
    END
    PORT
      LAYER Metal5 ;
        RECT 0.000 7.000 80.000 32.500 ;
    END
    PORT
      LAYER Metal5 ;
        RECT 0.000 126.000 80.000 134.000 ;
    END
    PORT
      LAYER Metal5 ;
        RECT 0.000 34.500 80.000 60.000 ;
    END
    PORT
      LAYER TopMetal1 ;
        RECT 0.000 7.000 80.000 32.500 ;
    END
    PORT
      LAYER TopMetal1 ;
        RECT 0.000 126.000 80.000 134.000 ;
    END
    PORT
      LAYER TopMetal1 ;
        RECT 0.000 34.500 80.000 60.000 ;
    END
    PORT
      LAYER TopMetal2 ;
        RECT 0.000 36.000 80.000 58.500 ;
    END
    PORT
      LAYER TopMetal2 ;
        RECT 0.000 8.500 80.000 31.000 ;
    END
    PORT
      LAYER TopMetal2 ;
        RECT 0.000 127.500 80.000 132.500 ;
    END
  END iovss
  PIN pad
    DIRECTION INOUT ;
    USE SIGNAL ;
    PORT
      LAYER Metal2 ;
        RECT 5.000 0.000 75.000 3.000 ;
      LAYER Metal3 ;
        RECT 5.000 0.000 75.000 3.000 ;
      LAYER Metal4 ;
        RECT 5.000 0.000 75.000 3.000 ;
      LAYER Metal5 ;
        RECT 5.000 0.000 75.000 3.000 ;
      LAYER TopMetal1 ;
        RECT 5.000 0.000 75.000 3.000 ;
      LAYER TopMetal2 ;
        RECT 5.000 0.000 75.000 3.000 ;
    END
  END pad
  PIN vdd
    DIRECTION INOUT ;
    USE POWER ;
    PORT
      LAYER Metal3 ;
        RECT 0.000 160.000 80.000 178.000 ;
    END
    PORT
      LAYER Metal4 ;
        RECT 0.000 140.000 80.000 155.800 ;
    END
    PORT
      LAYER Metal5 ;
        RECT 0.000 140.000 80.000 158.000 ;
    END
    PORT
      LAYER TopMetal1 ;
        RECT 0.000 140.000 80.000 158.000 ;
    END
  END vdd
  PIN vss
    DIRECTION INOUT ;
    USE GROUND ;
    PORT
      LAYER Metal3 ;
        RECT 0.000 140.000 80.000 158.000 ;
    END
    PORT
      LAYER Metal4 ;
        RECT 0.000 162.200 80.000 178.000 ;
    END
    PORT
      LAYER Metal5 ;
        RECT 0.000 160.000 80.000 178.000 ;
    END
    PORT
      LAYER TopMetal1 ;
        RECT 0.000 160.000 80.000 178.000 ;
    END
  END vss
  OBS
    LAYER Metal1 ;
      RECT 0.000 0.000 80.000 180.000 ;
    LAYER Metal2 ;
      RECT 0.000 0.000 80.000 180.000 ;
    LAYER Metal3 ;
      RECT 0.000 0.000 80.000 178.000 ;
    LAYER Metal4 ;
      RECT 0.000 0.000 80.000 178.000 ;
    LAYER Metal5 ;
      RECT 0.000 0.000 80.000 178.000 ;
    LAYER TopMetal1 ;
      RECT 0.000 0.000 80.000 178.000 ;
    LAYER TopMetal2 ;
      RECT 0.000 0.000 80.000 132.500 ;
    LAYER Via1 ;
      RECT 0.000 0.000 80.000 180.000 ;
    LAYER Via2 ;
      RECT 0.000 0.000 80.000 180.000 ;
  END
END sg13g2_IOPadOut4mA

MACRO sg13g2_IOPadOut16mA
    CLASS PAD OUTPUT ;
    ORIGIN 0.000 0.000 ;
    FOREIGN sg13g2_IOPadOut16mA 0.000 0.000 ;
    SIZE 80.000 BY 180.000 ;
    SYMMETRY X Y R90 ;
    SITE sg13g2_ioSite ;
  PIN c2p
    DIRECTION INPUT ;
    USE SIGNAL ;
    PORT
      LAYER Metal2 ;
        RECT 38.145 167.000 41.855 180.000 ;
      LAYER Metal3 ;
        RECT 38.145 179.710 41.855 180.000 ;
    END
  END c2p
  PIN iovdd
    DIRECTION INOUT ;
    USE POWER ;
    PORT
      LAYER Metal3 ;
        RECT 0.000 93.500 80.000 119.000 ;
    END
    PORT
      LAYER Metal3 ;
        RECT 0.000 66.000 80.000 91.500 ;
    END
    PORT
      LAYER Metal4 ;
        RECT 0.000 93.500 80.000 119.000 ;
    END
    PORT
      LAYER Metal4 ;
        RECT 0.000 66.000 80.000 91.500 ;
    END
    PORT
      LAYER Metal5 ;
        RECT 0.000 93.500 80.000 119.000 ;
    END
    PORT
      LAYER Metal5 ;
        RECT 0.000 66.000 80.000 91.500 ;
    END
    PORT
      LAYER TopMetal1 ;
        RECT 0.000 93.500 80.000 119.000 ;
    END
    PORT
      LAYER TopMetal1 ;
        RECT 0.000 66.000 80.000 91.500 ;
    END
    PORT
      LAYER TopMetal2 ;
        RECT 0.000 95.000 80.000 117.500 ;
    END
    PORT
      LAYER TopMetal2 ;
        RECT 0.000 67.500 80.000 90.000 ;
    END
  END iovdd
  PIN iovss
    DIRECTION INOUT ;
    USE GROUND ;
    PORT
      LAYER Metal3 ;
        RECT 0.000 7.000 80.000 32.500 ;
    END
    PORT
      LAYER Metal3 ;
        RECT 0.000 126.000 80.000 134.000 ;
    END
    PORT
      LAYER Metal3 ;
        RECT 0.000 34.500 80.000 60.000 ;
    END
    PORT
      LAYER Metal4 ;
        RECT 0.000 7.000 80.000 32.500 ;
    END
    PORT
      LAYER Metal4 ;
        RECT 0.000 126.000 80.000 134.000 ;
    END
    PORT
      LAYER Metal4 ;
        RECT 0.000 34.500 80.000 60.000 ;
    END
    PORT
      LAYER Metal5 ;
        RECT 0.000 7.000 80.000 32.500 ;
    END
    PORT
      LAYER Metal5 ;
        RECT 0.000 126.000 80.000 134.000 ;
    END
    PORT
      LAYER Metal5 ;
        RECT 0.000 34.500 80.000 60.000 ;
    END
    PORT
      LAYER TopMetal1 ;
        RECT 0.000 7.000 80.000 32.500 ;
    END
    PORT
      LAYER TopMetal1 ;
        RECT 0.000 126.000 80.000 134.000 ;
    END
    PORT
      LAYER TopMetal1 ;
        RECT 0.000 34.500 80.000 60.000 ;
    END
    PORT
      LAYER TopMetal2 ;
        RECT 0.000 36.000 80.000 58.500 ;
    END
    PORT
      LAYER TopMetal2 ;
        RECT 0.000 8.500 80.000 31.000 ;
    END
    PORT
      LAYER TopMetal2 ;
        RECT 0.000 127.500 80.000 132.500 ;
    END
  END iovss
  PIN pad
    DIRECTION INOUT ;
    USE SIGNAL ;
    PORT
      LAYER Metal2 ;
        RECT 5.000 0.000 75.000 3.000 ;
      LAYER Metal3 ;
        RECT 5.000 0.000 75.000 3.000 ;
      LAYER Metal4 ;
        RECT 5.000 0.000 75.000 3.000 ;
      LAYER Metal5 ;
        RECT 5.000 0.000 75.000 3.000 ;
      LAYER TopMetal1 ;
        RECT 5.000 0.000 75.000 3.000 ;
      LAYER TopMetal2 ;
        RECT 5.000 0.000 75.000 3.000 ;
    END
  END pad
  PIN vdd
    DIRECTION INOUT ;
    USE POWER ;
    PORT
      LAYER Metal3 ;
        RECT 0.000 160.000 80.000 178.000 ;
    END
    PORT
      LAYER Metal4 ;
        RECT 0.000 140.000 80.000 155.800 ;
    END
    PORT
      LAYER Metal5 ;
        RECT 0.000 140.000 80.000 158.000 ;
    END
    PORT
      LAYER TopMetal1 ;
        RECT 0.000 140.000 80.000 158.000 ;
    END
  END vdd
  PIN vss
    DIRECTION INOUT ;
    USE GROUND ;
    PORT
      LAYER Metal3 ;
        RECT 0.000 140.000 80.000 158.000 ;
    END
    PORT
      LAYER Metal4 ;
        RECT 0.000 162.200 80.000 178.000 ;
    END
    PORT
      LAYER Metal5 ;
        RECT 0.000 160.000 80.000 178.000 ;
    END
    PORT
      LAYER TopMetal1 ;
        RECT 0.000 160.000 80.000 178.000 ;
    END
  END vss
  OBS
    LAYER Metal1 ;
      RECT 0.000 0.000 80.000 180.000 ;
    LAYER Metal2 ;
      RECT 0.000 0.000 80.000 180.000 ;
    LAYER Metal3 ;
      RECT 0.000 0.000 80.000 178.000 ;
    LAYER Metal4 ;
      RECT 0.000 0.000 80.000 178.000 ;
    LAYER Metal5 ;
      RECT 0.000 0.000 80.000 178.000 ;
    LAYER TopMetal1 ;
      RECT 0.000 0.000 80.000 178.000 ;
    LAYER TopMetal2 ;
      RECT 0.000 0.000 80.000 132.500 ;
    LAYER Via1 ;
      RECT 0.000 0.000 80.000 180.000 ;
    LAYER Via2 ;
      RECT 0.000 0.000 80.000 180.000 ;
  END
END sg13g2_IOPadOut16mA

MACRO sg13g2_IOPadOut30mA
    CLASS PAD OUTPUT ;
    ORIGIN 0.000 0.000 ;
    FOREIGN sg13g2_IOPadOut30mA 0.000 0.000 ;
    SIZE 80.000 BY 180.000 ;
    SYMMETRY X Y R90 ;
    SITE sg13g2_ioSite ;
  PIN c2p
    DIRECTION INPUT ;
    USE SIGNAL ;
    PORT
      LAYER Metal2 ;
        RECT 38.145 167.000 41.855 180.000 ;
      LAYER Metal3 ;
        RECT 38.145 179.710 41.855 180.000 ;
    END
  END c2p
  PIN iovdd
    DIRECTION INOUT ;
    USE POWER ;
    PORT
      LAYER Metal3 ;
        RECT 0.000 93.500 80.000 119.000 ;
    END
    PORT
      LAYER Metal3 ;
        RECT 0.000 66.000 80.000 91.500 ;
    END
    PORT
      LAYER Metal4 ;
        RECT 0.000 93.500 80.000 119.000 ;
    END
    PORT
      LAYER Metal4 ;
        RECT 0.000 66.000 80.000 91.500 ;
    END
    PORT
      LAYER Metal5 ;
        RECT 0.000 93.500 80.000 119.000 ;
    END
    PORT
      LAYER Metal5 ;
        RECT 0.000 66.000 80.000 91.500 ;
    END
    PORT
      LAYER TopMetal1 ;
        RECT 0.000 93.500 80.000 119.000 ;
    END
    PORT
      LAYER TopMetal1 ;
        RECT 0.000 66.000 80.000 91.500 ;
    END
    PORT
      LAYER TopMetal2 ;
        RECT 0.000 95.000 80.000 117.500 ;
    END
    PORT
      LAYER TopMetal2 ;
        RECT 0.000 67.500 80.000 90.000 ;
    END
  END iovdd
  PIN iovss
    DIRECTION INOUT ;
    USE GROUND ;
    PORT
      LAYER Metal3 ;
        RECT 0.000 7.000 80.000 32.500 ;
    END
    PORT
      LAYER Metal3 ;
        RECT 0.000 126.000 80.000 134.000 ;
    END
    PORT
      LAYER Metal3 ;
        RECT 0.000 34.500 80.000 60.000 ;
    END
    PORT
      LAYER Metal4 ;
        RECT 0.000 7.000 80.000 32.500 ;
    END
    PORT
      LAYER Metal4 ;
        RECT 0.000 126.000 80.000 134.000 ;
    END
    PORT
      LAYER Metal4 ;
        RECT 0.000 34.500 80.000 60.000 ;
    END
    PORT
      LAYER Metal5 ;
        RECT 0.000 7.000 80.000 32.500 ;
    END
    PORT
      LAYER Metal5 ;
        RECT 0.000 126.000 80.000 134.000 ;
    END
    PORT
      LAYER Metal5 ;
        RECT 0.000 34.500 80.000 60.000 ;
    END
    PORT
      LAYER TopMetal1 ;
        RECT 0.000 7.000 80.000 32.500 ;
    END
    PORT
      LAYER TopMetal1 ;
        RECT 0.000 126.000 80.000 134.000 ;
    END
    PORT
      LAYER TopMetal1 ;
        RECT 0.000 34.500 80.000 60.000 ;
    END
    PORT
      LAYER TopMetal2 ;
        RECT 0.000 36.000 80.000 58.500 ;
    END
    PORT
      LAYER TopMetal2 ;
        RECT 0.000 8.500 80.000 31.000 ;
    END
    PORT
      LAYER TopMetal2 ;
        RECT 0.000 127.500 80.000 132.500 ;
    END
  END iovss
  PIN pad
    DIRECTION INOUT ;
    USE SIGNAL ;
    PORT
      LAYER Metal2 ;
        RECT 5.000 0.000 75.000 3.000 ;
      LAYER Metal3 ;
        RECT 5.000 0.000 75.000 3.000 ;
      LAYER Metal4 ;
        RECT 5.000 0.000 75.000 3.000 ;
      LAYER Metal5 ;
        RECT 5.000 0.000 75.000 3.000 ;
      LAYER TopMetal1 ;
        RECT 5.000 0.000 75.000 3.000 ;
      LAYER TopMetal2 ;
        RECT 5.000 0.000 75.000 3.000 ;
    END
  END pad
  PIN vdd
    DIRECTION INOUT ;
    USE POWER ;
    PORT
      LAYER Metal3 ;
        RECT 0.000 160.000 80.000 178.000 ;
    END
    PORT
      LAYER Metal4 ;
        RECT 0.000 140.000 80.000 155.800 ;
    END
    PORT
      LAYER Metal5 ;
        RECT 0.000 140.000 80.000 158.000 ;
    END
    PORT
      LAYER TopMetal1 ;
        RECT 0.000 140.000 80.000 158.000 ;
    END
  END vdd
  PIN vss
    DIRECTION INOUT ;
    USE GROUND ;
    PORT
      LAYER Metal3 ;
        RECT 0.000 140.000 80.000 158.000 ;
    END
    PORT
      LAYER Metal4 ;
        RECT 0.000 162.200 80.000 178.000 ;
    END
    PORT
      LAYER Metal5 ;
        RECT 0.000 160.000 80.000 178.000 ;
    END
    PORT
      LAYER TopMetal1 ;
        RECT 0.000 160.000 80.000 178.000 ;
    END
  END vss
  OBS
    LAYER Metal1 ;
      RECT 0.000 0.000 80.000 180.000 ;
    LAYER Metal2 ;
      RECT 0.000 0.000 80.000 180.000 ;
    LAYER Metal3 ;
      RECT 0.000 0.000 80.000 178.000 ;
    LAYER Metal4 ;
      RECT 0.000 0.000 80.000 178.000 ;
    LAYER Metal5 ;
      RECT 0.000 0.000 80.000 178.000 ;
    LAYER TopMetal1 ;
      RECT 0.000 0.000 80.000 178.000 ;
    LAYER TopMetal2 ;
      RECT 0.000 0.000 80.000 132.500 ;
    LAYER Via1 ;
      RECT 0.000 0.000 80.000 180.000 ;
    LAYER Via2 ;
      RECT 0.000 0.000 80.000 180.000 ;
  END
END sg13g2_IOPadOut30mA

MACRO sg13g2_IOPadTriOut4mA
    CLASS PAD OUTPUT ;
    ORIGIN 0.000 0.000 ;
    FOREIGN sg13g2_IOPadTriOut4mA 0.000 0.000 ;
    SIZE 80.000 BY 180.000 ;
    SYMMETRY X Y R90 ;
    SITE sg13g2_ioSite ;
  PIN c2p
    DIRECTION INPUT ;
    USE SIGNAL ;
    PORT
      LAYER Metal2 ;
        RECT 38.330 178.090 38.620 180.000 ;
      LAYER Metal3 ;
        RECT 38.225 179.710 38.725 180.000 ;
    END
  END c2p
  PIN c2p_en
    DIRECTION INPUT ;
    USE SIGNAL ;
    PORT
      LAYER Metal2 ;
        RECT 41.380 174.045 41.670 180.000 ;
      LAYER Metal3 ;
        RECT 41.275 179.710 41.775 180.000 ;
    END
  END c2p_en
  PIN iovdd
    DIRECTION INOUT ;
    USE POWER ;
    PORT
      LAYER Metal3 ;
        RECT 0.000 93.500 80.000 119.000 ;
    END
    PORT
      LAYER Metal3 ;
        RECT 0.000 66.000 80.000 91.500 ;
    END
    PORT
      LAYER Metal4 ;
        RECT 0.000 93.500 80.000 119.000 ;
    END
    PORT
      LAYER Metal4 ;
        RECT 0.000 66.000 80.000 91.500 ;
    END
    PORT
      LAYER Metal5 ;
        RECT 0.000 93.500 80.000 119.000 ;
    END
    PORT
      LAYER Metal5 ;
        RECT 0.000 66.000 80.000 91.500 ;
    END
    PORT
      LAYER TopMetal1 ;
        RECT 0.000 93.500 80.000 119.000 ;
    END
    PORT
      LAYER TopMetal1 ;
        RECT 0.000 66.000 80.000 91.500 ;
    END
    PORT
      LAYER TopMetal2 ;
        RECT 0.000 95.000 80.000 117.500 ;
    END
    PORT
      LAYER TopMetal2 ;
        RECT 0.000 67.500 80.000 90.000 ;
    END
  END iovdd
  PIN iovss
    DIRECTION INOUT ;
    USE GROUND ;
    PORT
      LAYER Metal3 ;
        RECT 0.000 7.000 80.000 32.500 ;
    END
    PORT
      LAYER Metal3 ;
        RECT 0.000 126.000 80.000 134.000 ;
    END
    PORT
      LAYER Metal3 ;
        RECT 0.000 34.500 80.000 60.000 ;
    END
    PORT
      LAYER Metal4 ;
        RECT 0.000 7.000 80.000 32.500 ;
    END
    PORT
      LAYER Metal4 ;
        RECT 0.000 126.000 80.000 134.000 ;
    END
    PORT
      LAYER Metal4 ;
        RECT 0.000 34.500 80.000 60.000 ;
    END
    PORT
      LAYER Metal5 ;
        RECT 0.000 7.000 80.000 32.500 ;
    END
    PORT
      LAYER Metal5 ;
        RECT 0.000 126.000 80.000 134.000 ;
    END
    PORT
      LAYER Metal5 ;
        RECT 0.000 34.500 80.000 60.000 ;
    END
    PORT
      LAYER TopMetal1 ;
        RECT 0.000 7.000 80.000 32.500 ;
    END
    PORT
      LAYER TopMetal1 ;
        RECT 0.000 126.000 80.000 134.000 ;
    END
    PORT
      LAYER TopMetal1 ;
        RECT 0.000 34.500 80.000 60.000 ;
    END
    PORT
      LAYER TopMetal2 ;
        RECT 0.000 36.000 80.000 58.500 ;
    END
    PORT
      LAYER TopMetal2 ;
        RECT 0.000 8.500 80.000 31.000 ;
    END
    PORT
      LAYER TopMetal2 ;
        RECT 0.000 127.500 80.000 132.500 ;
    END
  END iovss
  PIN pad
    DIRECTION INOUT ;
    USE SIGNAL ;
    PORT
      LAYER Metal2 ;
        RECT 5.000 0.000 75.000 3.000 ;
      LAYER Metal3 ;
        RECT 5.000 0.000 75.000 3.000 ;
      LAYER Metal4 ;
        RECT 5.000 0.000 75.000 3.000 ;
      LAYER Metal5 ;
        RECT 5.000 0.000 75.000 3.000 ;
      LAYER TopMetal1 ;
        RECT 5.000 0.000 75.000 3.000 ;
      LAYER TopMetal2 ;
        RECT 5.000 0.000 75.000 3.000 ;
    END
  END pad
  PIN vdd
    DIRECTION INOUT ;
    USE POWER ;
    PORT
      LAYER Metal3 ;
        RECT 0.000 160.000 80.000 178.000 ;
    END
    PORT
      LAYER Metal4 ;
        RECT 0.000 140.000 80.000 155.800 ;
    END
    PORT
      LAYER Metal5 ;
        RECT 0.000 140.000 80.000 158.000 ;
    END
    PORT
      LAYER TopMetal1 ;
        RECT 0.000 140.000 80.000 158.000 ;
    END
  END vdd
  PIN vss
    DIRECTION INOUT ;
    USE GROUND ;
    PORT
      LAYER Metal3 ;
        RECT 0.000 140.000 80.000 158.000 ;
    END
    PORT
      LAYER Metal4 ;
        RECT 0.000 162.200 80.000 178.000 ;
    END
    PORT
      LAYER Metal5 ;
        RECT 0.000 160.000 80.000 178.000 ;
    END
    PORT
      LAYER TopMetal1 ;
        RECT 0.000 160.000 80.000 178.000 ;
    END
  END vss
  OBS
    LAYER Metal1 ;
      RECT 0.000 0.000 80.000 180.000 ;
    LAYER Metal2 ;
      RECT 0.000 0.000 80.000 180.000 ;
    LAYER Metal3 ;
      RECT 0.000 0.000 80.000 178.000 ;
    LAYER Metal4 ;
      RECT 0.000 0.000 80.000 178.000 ;
    LAYER Metal5 ;
      RECT 0.000 0.000 80.000 178.000 ;
    LAYER TopMetal1 ;
      RECT 0.000 0.000 80.000 178.000 ;
    LAYER TopMetal2 ;
      RECT 0.000 0.000 80.000 132.500 ;
    LAYER Via1 ;
      RECT 0.000 0.000 80.000 180.000 ;
    LAYER Via2 ;
      RECT 0.000 0.000 80.000 180.000 ;
  END
END sg13g2_IOPadTriOut4mA

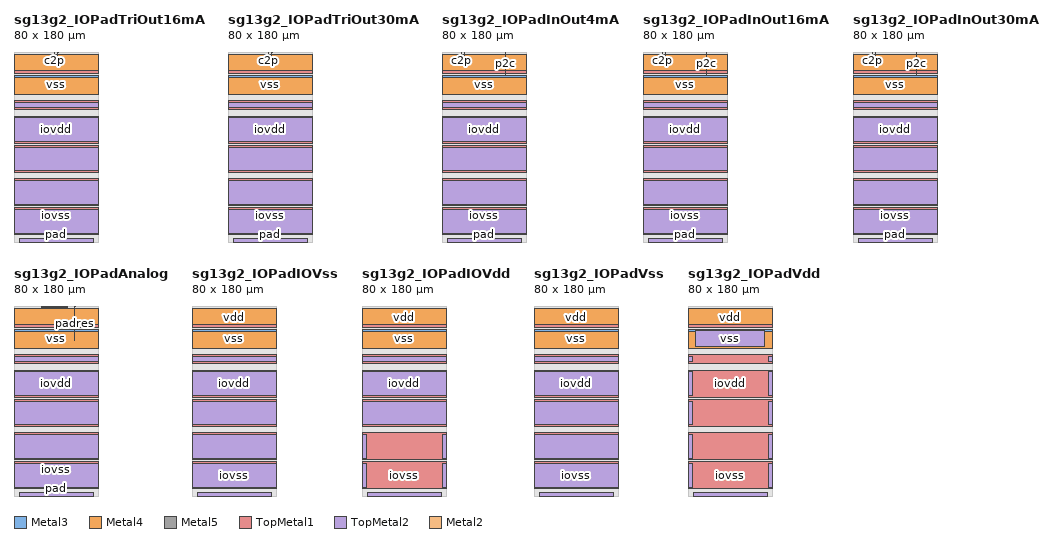
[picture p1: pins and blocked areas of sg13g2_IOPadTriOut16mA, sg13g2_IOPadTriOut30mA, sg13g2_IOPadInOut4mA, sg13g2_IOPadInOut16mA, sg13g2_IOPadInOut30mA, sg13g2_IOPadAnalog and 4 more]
MACRO sg13g2_IOPadTriOut16mA
    CLASS PAD OUTPUT ;
    ORIGIN 0.000 0.000 ;
    FOREIGN sg13g2_IOPadTriOut16mA 0.000 0.000 ;
    SIZE 80.000 BY 180.000 ;
    SYMMETRY X Y R90 ;
    SITE sg13g2_ioSite ;
  PIN c2p
    DIRECTION INPUT ;
    USE SIGNAL ;
    PORT
      LAYER Metal2 ;
        RECT 38.330 178.090 38.620 180.000 ;
      LAYER Metal3 ;
        RECT 38.225 179.710 38.725 180.000 ;
    END
  END c2p
  PIN c2p_en
    DIRECTION INPUT ;
    USE SIGNAL ;
    PORT
      LAYER Metal2 ;
        RECT 41.380 174.045 41.670 180.000 ;
      LAYER Metal3 ;
        RECT 41.275 179.710 41.775 180.000 ;
    END
  END c2p_en
  PIN iovdd
    DIRECTION INOUT ;
    USE POWER ;
    PORT
      LAYER Metal3 ;
        RECT 0.000 93.500 80.000 119.000 ;
    END
    PORT
      LAYER Metal3 ;
        RECT 0.000 66.000 80.000 91.500 ;
    END
    PORT
      LAYER Metal4 ;
        RECT 0.000 93.500 80.000 119.000 ;
    END
    PORT
      LAYER Metal4 ;
        RECT 0.000 66.000 80.000 91.500 ;
    END
    PORT
      LAYER Metal5 ;
        RECT 0.000 93.500 80.000 119.000 ;
    END
    PORT
      LAYER Metal5 ;
        RECT 0.000 66.000 80.000 91.500 ;
    END
    PORT
      LAYER TopMetal1 ;
        RECT 0.000 93.500 80.000 119.000 ;
    END
    PORT
      LAYER TopMetal1 ;
        RECT 0.000 66.000 80.000 91.500 ;
    END
    PORT
      LAYER TopMetal2 ;
        RECT 0.000 95.000 80.000 117.500 ;
    END
    PORT
      LAYER TopMetal2 ;
        RECT 0.000 67.500 80.000 90.000 ;
    END
  END iovdd
  PIN iovss
    DIRECTION INOUT ;
    USE GROUND ;
    PORT
      LAYER Metal3 ;
        RECT 0.000 7.000 80.000 32.500 ;
    END
    PORT
      LAYER Metal3 ;
        RECT 0.000 126.000 80.000 134.000 ;
    END
    PORT
      LAYER Metal3 ;
        RECT 0.000 34.500 80.000 60.000 ;
    END
    PORT
      LAYER Metal4 ;
        RECT 0.000 7.000 80.000 32.500 ;
    END
    PORT
      LAYER Metal4 ;
        RECT 0.000 126.000 80.000 134.000 ;
    END
    PORT
      LAYER Metal4 ;
        RECT 0.000 34.500 80.000 60.000 ;
    END
    PORT
      LAYER Metal5 ;
        RECT 0.000 7.000 80.000 32.500 ;
    END
    PORT
      LAYER Metal5 ;
        RECT 0.000 126.000 80.000 134.000 ;
    END
    PORT
      LAYER Metal5 ;
        RECT 0.000 34.500 80.000 60.000 ;
    END
    PORT
      LAYER TopMetal1 ;
        RECT 0.000 7.000 80.000 32.500 ;
    END
    PORT
      LAYER TopMetal1 ;
        RECT 0.000 126.000 80.000 134.000 ;
    END
    PORT
      LAYER TopMetal1 ;
        RECT 0.000 34.500 80.000 60.000 ;
    END
    PORT
      LAYER TopMetal2 ;
        RECT 0.000 36.000 80.000 58.500 ;
    END
    PORT
      LAYER TopMetal2 ;
        RECT 0.000 8.500 80.000 31.000 ;
    END
    PORT
      LAYER TopMetal2 ;
        RECT 0.000 127.500 80.000 132.500 ;
    END
  END iovss
  PIN pad
    DIRECTION INOUT ;
    USE SIGNAL ;
    PORT
      LAYER Metal2 ;
        RECT 5.000 0.000 75.000 3.000 ;
      LAYER Metal3 ;
        RECT 5.000 0.000 75.000 3.000 ;
      LAYER Metal4 ;
        RECT 5.000 0.000 75.000 3.000 ;
      LAYER Metal5 ;
        RECT 5.000 0.000 75.000 3.000 ;
      LAYER TopMetal1 ;
        RECT 5.000 0.000 75.000 3.000 ;
      LAYER TopMetal2 ;
        RECT 5.000 0.000 75.000 3.000 ;
    END
  END pad
  PIN vdd
    DIRECTION INOUT ;
    USE POWER ;
    PORT
      LAYER Metal3 ;
        RECT 0.000 160.000 80.000 178.000 ;
    END
    PORT
      LAYER Metal4 ;
        RECT 0.000 140.000 80.000 155.800 ;
    END
    PORT
      LAYER Metal5 ;
        RECT 0.000 140.000 80.000 158.000 ;
    END
    PORT
      LAYER TopMetal1 ;
        RECT 0.000 140.000 80.000 158.000 ;
    END
  END vdd
  PIN vss
    DIRECTION INOUT ;
    USE GROUND ;
    PORT
      LAYER Metal3 ;
        RECT 0.000 140.000 80.000 158.000 ;
    END
    PORT
      LAYER Metal4 ;
        RECT 0.000 162.200 80.000 178.000 ;
    END
    PORT
      LAYER Metal5 ;
        RECT 0.000 160.000 80.000 178.000 ;
    END
    PORT
      LAYER TopMetal1 ;
        RECT 0.000 160.000 80.000 178.000 ;
    END
  END vss
  OBS
    LAYER Metal1 ;
      RECT 0.000 0.000 80.000 180.000 ;
    LAYER Metal2 ;
      RECT 0.000 0.000 80.000 180.000 ;
    LAYER Metal3 ;
      RECT 0.000 0.000 80.000 178.000 ;
    LAYER Metal4 ;
      RECT 0.000 0.000 80.000 178.000 ;
    LAYER Metal5 ;
      RECT 0.000 0.000 80.000 178.000 ;
    LAYER TopMetal1 ;
      RECT 0.000 0.000 80.000 178.000 ;
    LAYER TopMetal2 ;
      RECT 0.000 0.000 80.000 132.500 ;
    LAYER Via1 ;
      RECT 0.000 0.000 80.000 180.000 ;
    LAYER Via2 ;
      RECT 0.000 0.000 80.000 180.000 ;
  END
END sg13g2_IOPadTriOut16mA

MACRO sg13g2_IOPadTriOut30mA
    CLASS PAD OUTPUT ;
    ORIGIN 0.000 0.000 ;
    FOREIGN sg13g2_IOPadTriOut30mA 0.000 0.000 ;
    SIZE 80.000 BY 180.000 ;
    SYMMETRY X Y R90 ;
    SITE sg13g2_ioSite ;
  PIN c2p
    DIRECTION INPUT ;
    USE SIGNAL ;
    PORT
      LAYER Metal2 ;
        RECT 38.330 178.090 38.620 180.000 ;
      LAYER Metal3 ;
        RECT 38.225 179.710 38.725 180.000 ;
    END
  END c2p
  PIN c2p_en
    DIRECTION INPUT ;
    USE SIGNAL ;
    PORT
      LAYER Metal2 ;
        RECT 41.380 174.045 41.670 180.000 ;
      LAYER Metal3 ;
        RECT 41.275 179.710 41.775 180.000 ;
    END
  END c2p_en
  PIN iovdd
    DIRECTION INOUT ;
    USE POWER ;
    PORT
      LAYER Metal3 ;
        RECT 0.000 93.500 80.000 119.000 ;
    END
    PORT
      LAYER Metal3 ;
        RECT 0.000 66.000 80.000 91.500 ;
    END
    PORT
      LAYER Metal4 ;
        RECT 0.000 93.500 80.000 119.000 ;
    END
    PORT
      LAYER Metal4 ;
        RECT 0.000 66.000 80.000 91.500 ;
    END
    PORT
      LAYER Metal5 ;
        RECT 0.000 93.500 80.000 119.000 ;
    END
    PORT
      LAYER Metal5 ;
        RECT 0.000 66.000 80.000 91.500 ;
    END
    PORT
      LAYER TopMetal1 ;
        RECT 0.000 93.500 80.000 119.000 ;
    END
    PORT
      LAYER TopMetal1 ;
        RECT 0.000 66.000 80.000 91.500 ;
    END
    PORT
      LAYER TopMetal2 ;
        RECT 0.000 95.000 80.000 117.500 ;
    END
    PORT
      LAYER TopMetal2 ;
        RECT 0.000 67.500 80.000 90.000 ;
    END
  END iovdd
  PIN iovss
    DIRECTION INOUT ;
    USE GROUND ;
    PORT
      LAYER Metal3 ;
        RECT 0.000 7.000 80.000 32.500 ;
    END
    PORT
      LAYER Metal3 ;
        RECT 0.000 126.000 80.000 134.000 ;
    END
    PORT
      LAYER Metal3 ;
        RECT 0.000 34.500 80.000 60.000 ;
    END
    PORT
      LAYER Metal4 ;
        RECT 0.000 7.000 80.000 32.500 ;
    END
    PORT
      LAYER Metal4 ;
        RECT 0.000 126.000 80.000 134.000 ;
    END
    PORT
      LAYER Metal4 ;
        RECT 0.000 34.500 80.000 60.000 ;
    END
    PORT
      LAYER Metal5 ;
        RECT 0.000 7.000 80.000 32.500 ;
    END
    PORT
      LAYER Metal5 ;
        RECT 0.000 126.000 80.000 134.000 ;
    END
    PORT
      LAYER Metal5 ;
        RECT 0.000 34.500 80.000 60.000 ;
    END
    PORT
      LAYER TopMetal1 ;
        RECT 0.000 7.000 80.000 32.500 ;
    END
    PORT
      LAYER TopMetal1 ;
        RECT 0.000 126.000 80.000 134.000 ;
    END
    PORT
      LAYER TopMetal1 ;
        RECT 0.000 34.500 80.000 60.000 ;
    END
    PORT
      LAYER TopMetal2 ;
        RECT 0.000 36.000 80.000 58.500 ;
    END
    PORT
      LAYER TopMetal2 ;
        RECT 0.000 8.500 80.000 31.000 ;
    END
    PORT
      LAYER TopMetal2 ;
        RECT 0.000 127.500 80.000 132.500 ;
    END
  END iovss
  PIN pad
    DIRECTION INOUT ;
    USE SIGNAL ;
    PORT
      LAYER Metal2 ;
        RECT 5.000 0.000 75.000 3.000 ;
      LAYER Metal3 ;
        RECT 5.000 0.000 75.000 3.000 ;
      LAYER Metal4 ;
        RECT 5.000 0.000 75.000 3.000 ;
      LAYER Metal5 ;
        RECT 5.000 0.000 75.000 3.000 ;
      LAYER TopMetal1 ;
        RECT 5.000 0.000 75.000 3.000 ;
      LAYER TopMetal2 ;
        RECT 5.000 0.000 75.000 3.000 ;
    END
  END pad
  PIN vdd
    DIRECTION INOUT ;
    USE POWER ;
    PORT
      LAYER Metal3 ;
        RECT 0.000 160.000 80.000 178.000 ;
    END
    PORT
      LAYER Metal4 ;
        RECT 0.000 140.000 80.000 155.800 ;
    END
    PORT
      LAYER Metal5 ;
        RECT 0.000 140.000 80.000 158.000 ;
    END
    PORT
      LAYER TopMetal1 ;
        RECT 0.000 140.000 80.000 158.000 ;
    END
  END vdd
  PIN vss
    DIRECTION INOUT ;
    USE GROUND ;
    PORT
      LAYER Metal3 ;
        RECT 0.000 140.000 80.000 158.000 ;
    END
    PORT
      LAYER Metal4 ;
        RECT 0.000 162.200 80.000 178.000 ;
    END
    PORT
      LAYER Metal5 ;
        RECT 0.000 160.000 80.000 178.000 ;
    END
    PORT
      LAYER TopMetal1 ;
        RECT 0.000 160.000 80.000 178.000 ;
    END
  END vss
  OBS
    LAYER Metal1 ;
      RECT 0.000 0.000 80.000 180.000 ;
    LAYER Metal2 ;
      RECT 0.000 0.000 80.000 180.000 ;
    LAYER Metal3 ;
      RECT 0.000 0.000 80.000 178.000 ;
    LAYER Metal4 ;
      RECT 0.000 0.000 80.000 178.000 ;
    LAYER Metal5 ;
      RECT 0.000 0.000 80.000 178.000 ;
    LAYER TopMetal1 ;
      RECT 0.000 0.000 80.000 178.000 ;
    LAYER TopMetal2 ;
      RECT 0.000 0.000 80.000 132.500 ;
    LAYER Via1 ;
      RECT 0.000 0.000 80.000 180.000 ;
    LAYER Via2 ;
      RECT 0.000 0.000 80.000 180.000 ;
  END
END sg13g2_IOPadTriOut30mA

MACRO sg13g2_IOPadInOut4mA
    CLASS PAD INOUT ;
    ORIGIN 0.000 0.000 ;
    FOREIGN sg13g2_IOPadInOut4mA 0.000 0.000 ;
    SIZE 80.000 BY 180.000 ;
    SYMMETRY X Y R90 ;
    SITE sg13g2_ioSite ;
  PIN c2p
    DIRECTION INPUT ;
    USE SIGNAL ;
    PORT
      LAYER Metal2 ;
        RECT 18.330 178.090 18.620 180.000 ;
      LAYER Metal3 ;
        RECT 18.225 179.710 18.725 180.000 ;
    END
  END c2p
  PIN c2p_en
    DIRECTION INPUT ;
    USE SIGNAL ;
    PORT
      LAYER Metal2 ;
        RECT 21.380 174.045 21.670 180.000 ;
      LAYER Metal3 ;
        RECT 21.275 179.710 21.775 180.000 ;
    END
  END c2p_en
  PIN iovdd
    DIRECTION INOUT ;
    USE POWER ;
    PORT
      LAYER Metal3 ;
        RECT 0.000 93.500 80.000 119.000 ;
    END
    PORT
      LAYER Metal3 ;
        RECT 0.000 66.000 80.000 91.500 ;
    END
    PORT
      LAYER Metal4 ;
        RECT 0.000 93.500 80.000 119.000 ;
    END
    PORT
      LAYER Metal4 ;
        RECT 0.000 66.000 80.000 91.500 ;
    END
    PORT
      LAYER Metal5 ;
        RECT 0.000 93.500 80.000 119.000 ;
    END
    PORT
      LAYER Metal5 ;
        RECT 0.000 66.000 80.000 91.500 ;
    END
    PORT
      LAYER TopMetal1 ;
        RECT 0.000 93.500 80.000 119.000 ;
    END
    PORT
      LAYER TopMetal1 ;
        RECT 0.000 66.000 80.000 91.500 ;
    END
    PORT
      LAYER TopMetal2 ;
        RECT 0.000 95.000 80.000 117.500 ;
    END
    PORT
      LAYER TopMetal2 ;
        RECT 0.000 67.500 80.000 90.000 ;
    END
  END iovdd
  PIN iovss
    DIRECTION INOUT ;
    USE GROUND ;
    PORT
      LAYER Metal3 ;
        RECT 0.000 7.000 80.000 32.500 ;
    END
    PORT
      LAYER Metal3 ;
        RECT 0.000 126.000 80.000 134.000 ;
    END
    PORT
      LAYER Metal3 ;
        RECT 0.000 34.500 80.000 60.000 ;
    END
    PORT
      LAYER Metal4 ;
        RECT 0.000 7.000 80.000 32.500 ;
    END
    PORT
      LAYER Metal4 ;
        RECT 0.000 126.000 80.000 134.000 ;
    END
    PORT
      LAYER Metal4 ;
        RECT 0.000 34.500 80.000 60.000 ;
    END
    PORT
      LAYER Metal5 ;
        RECT 0.000 7.000 80.000 32.500 ;
    END
    PORT
      LAYER Metal5 ;
        RECT 0.000 126.000 80.000 134.000 ;
    END
    PORT
      LAYER Metal5 ;
        RECT 0.000 34.500 80.000 60.000 ;
    END
    PORT
      LAYER TopMetal1 ;
        RECT 0.000 7.000 80.000 32.500 ;
    END
    PORT
      LAYER TopMetal1 ;
        RECT 0.000 126.000 80.000 134.000 ;
    END
    PORT
      LAYER TopMetal1 ;
        RECT 0.000 34.500 80.000 60.000 ;
    END
    PORT
      LAYER TopMetal2 ;
        RECT 0.000 36.000 80.000 58.500 ;
    END
    PORT
      LAYER TopMetal2 ;
        RECT 0.000 8.500 80.000 31.000 ;
    END
    PORT
      LAYER TopMetal2 ;
        RECT 0.000 127.500 80.000 132.500 ;
    END
  END iovss
  PIN p2c
    DIRECTION OUTPUT ;
    USE SIGNAL ;
    PORT
      LAYER Metal2 ;
        RECT 59.830 157.810 60.120 180.000 ;
      LAYER Metal3 ;
        RECT 59.725 179.710 60.225 180.000 ;
    END
  END p2c
  PIN pad
    DIRECTION INOUT ;
    USE SIGNAL ;
    PORT
      LAYER Metal2 ;
        RECT 5.000 0.000 75.000 3.000 ;
      LAYER Metal3 ;
        RECT 5.000 0.000 75.000 3.000 ;
      LAYER Metal4 ;
        RECT 5.000 0.000 75.000 3.000 ;
      LAYER Metal5 ;
        RECT 5.000 0.000 75.000 3.000 ;
      LAYER TopMetal1 ;
        RECT 5.000 0.000 75.000 3.000 ;
      LAYER TopMetal2 ;
        RECT 5.000 0.000 75.000 3.000 ;
    END
  END pad
  PIN vdd
    DIRECTION INOUT ;
    USE POWER ;
    PORT
      LAYER Metal3 ;
        RECT 0.000 160.000 80.000 178.000 ;
    END
    PORT
      LAYER Metal4 ;
        RECT 0.000 140.000 80.000 155.800 ;
    END
    PORT
      LAYER Metal5 ;
        RECT 0.000 140.000 80.000 158.000 ;
    END
    PORT
      LAYER TopMetal1 ;
        RECT 0.000 140.000 80.000 158.000 ;
    END
  END vdd
  PIN vss
    DIRECTION INOUT ;
    USE GROUND ;
    PORT
      LAYER Metal3 ;
        RECT 0.000 140.000 80.000 158.000 ;
    END
    PORT
      LAYER Metal4 ;
        RECT 0.000 162.200 80.000 178.000 ;
    END
    PORT
      LAYER Metal5 ;
        RECT 0.000 160.000 80.000 178.000 ;
    END
    PORT
      LAYER TopMetal1 ;
        RECT 0.000 160.000 80.000 178.000 ;
    END
  END vss
  OBS
    LAYER Metal1 ;
      RECT 0.000 0.000 80.000 180.000 ;
    LAYER Metal2 ;
      RECT 0.000 0.000 80.000 180.000 ;
    LAYER Metal3 ;
      RECT 0.000 0.000 80.000 178.000 ;
    LAYER Metal4 ;
      RECT 0.000 0.000 80.000 178.000 ;
    LAYER Metal5 ;
      RECT 0.000 0.000 80.000 178.000 ;
    LAYER TopMetal1 ;
      RECT 0.000 0.000 80.000 178.000 ;
    LAYER TopMetal2 ;
      RECT 0.000 0.000 80.000 132.500 ;
    LAYER Via1 ;
      RECT 0.000 0.000 80.000 180.000 ;
    LAYER Via2 ;
      RECT 0.000 0.000 80.000 180.000 ;
  END
END sg13g2_IOPadInOut4mA

MACRO sg13g2_IOPadInOut16mA
    CLASS PAD INOUT ;
    ORIGIN 0.000 0.000 ;
    FOREIGN sg13g2_IOPadInOut16mA 0.000 0.000 ;
    SIZE 80.000 BY 180.000 ;
    SYMMETRY X Y R90 ;
    SITE sg13g2_ioSite ;
  PIN c2p
    DIRECTION INPUT ;
    USE SIGNAL ;
    PORT
      LAYER Metal2 ;
        RECT 18.330 178.090 18.620 180.000 ;
      LAYER Metal3 ;
        RECT 18.225 179.710 18.725 180.000 ;
    END
  END c2p
  PIN c2p_en
    DIRECTION INPUT ;
    USE SIGNAL ;
    PORT
      LAYER Metal2 ;
        RECT 21.380 174.045 21.670 180.000 ;
      LAYER Metal3 ;
        RECT 21.275 179.710 21.775 180.000 ;
    END
  END c2p_en
  PIN iovdd
    DIRECTION INOUT ;
    USE POWER ;
    PORT
      LAYER Metal3 ;
        RECT 0.000 93.500 80.000 119.000 ;
    END
    PORT
      LAYER Metal3 ;
        RECT 0.000 66.000 80.000 91.500 ;
    END
    PORT
      LAYER Metal4 ;
        RECT 0.000 93.500 80.000 119.000 ;
    END
    PORT
      LAYER Metal4 ;
        RECT 0.000 66.000 80.000 91.500 ;
    END
    PORT
      LAYER Metal5 ;
        RECT 0.000 93.500 80.000 119.000 ;
    END
    PORT
      LAYER Metal5 ;
        RECT 0.000 66.000 80.000 91.500 ;
    END
    PORT
      LAYER TopMetal1 ;
        RECT 0.000 93.500 80.000 119.000 ;
    END
    PORT
      LAYER TopMetal1 ;
        RECT 0.000 66.000 80.000 91.500 ;
    END
    PORT
      LAYER TopMetal2 ;
        RECT 0.000 95.000 80.000 117.500 ;
    END
    PORT
      LAYER TopMetal2 ;
        RECT 0.000 67.500 80.000 90.000 ;
    END
  END iovdd
  PIN iovss
    DIRECTION INOUT ;
    USE GROUND ;
    PORT
      LAYER Metal3 ;
        RECT 0.000 7.000 80.000 32.500 ;
    END
    PORT
      LAYER Metal3 ;
        RECT 0.000 126.000 80.000 134.000 ;
    END
    PORT
      LAYER Metal3 ;
        RECT 0.000 34.500 80.000 60.000 ;
    END
    PORT
      LAYER Metal4 ;
        RECT 0.000 7.000 80.000 32.500 ;
    END
    PORT
      LAYER Metal4 ;
        RECT 0.000 126.000 80.000 134.000 ;
    END
    PORT
      LAYER Metal4 ;
        RECT 0.000 34.500 80.000 60.000 ;
    END
    PORT
      LAYER Metal5 ;
        RECT 0.000 7.000 80.000 32.500 ;
    END
    PORT
      LAYER Metal5 ;
        RECT 0.000 126.000 80.000 134.000 ;
    END
    PORT
      LAYER Metal5 ;
        RECT 0.000 34.500 80.000 60.000 ;
    END
    PORT
      LAYER TopMetal1 ;
        RECT 0.000 7.000 80.000 32.500 ;
    END
    PORT
      LAYER TopMetal1 ;
        RECT 0.000 126.000 80.000 134.000 ;
    END
    PORT
      LAYER TopMetal1 ;
        RECT 0.000 34.500 80.000 60.000 ;
    END
    PORT
      LAYER TopMetal2 ;
        RECT 0.000 36.000 80.000 58.500 ;
    END
    PORT
      LAYER TopMetal2 ;
        RECT 0.000 8.500 80.000 31.000 ;
    END
    PORT
      LAYER TopMetal2 ;
        RECT 0.000 127.500 80.000 132.500 ;
    END
  END iovss
  PIN p2c
    DIRECTION OUTPUT ;
    USE SIGNAL ;
    PORT
      LAYER Metal2 ;
        RECT 59.830 157.810 60.120 180.000 ;
      LAYER Metal3 ;
        RECT 59.725 179.710 60.225 180.000 ;
    END
  END p2c
  PIN pad
    DIRECTION INOUT ;
    USE SIGNAL ;
    PORT
      LAYER Metal2 ;
        RECT 5.000 0.000 75.000 3.000 ;
      LAYER Metal3 ;
        RECT 5.000 0.000 75.000 3.000 ;
      LAYER Metal4 ;
        RECT 5.000 0.000 75.000 3.000 ;
      LAYER Metal5 ;
        RECT 5.000 0.000 75.000 3.000 ;
      LAYER TopMetal1 ;
        RECT 5.000 0.000 75.000 3.000 ;
      LAYER TopMetal2 ;
        RECT 5.000 0.000 75.000 3.000 ;
    END
  END pad
  PIN vdd
    DIRECTION INOUT ;
    USE POWER ;
    PORT
      LAYER Metal3 ;
        RECT 0.000 160.000 80.000 178.000 ;
    END
    PORT
      LAYER Metal4 ;
        RECT 0.000 140.000 80.000 155.800 ;
    END
    PORT
      LAYER Metal5 ;
        RECT 0.000 140.000 80.000 158.000 ;
    END
    PORT
      LAYER TopMetal1 ;
        RECT 0.000 140.000 80.000 158.000 ;
    END
  END vdd
  PIN vss
    DIRECTION INOUT ;
    USE GROUND ;
    PORT
      LAYER Metal3 ;
        RECT 0.000 140.000 80.000 158.000 ;
    END
    PORT
      LAYER Metal4 ;
        RECT 0.000 162.200 80.000 178.000 ;
    END
    PORT
      LAYER Metal5 ;
        RECT 0.000 160.000 80.000 178.000 ;
    END
    PORT
      LAYER TopMetal1 ;
        RECT 0.000 160.000 80.000 178.000 ;
    END
  END vss
  OBS
    LAYER Metal1 ;
      RECT 0.000 0.000 80.000 180.000 ;
    LAYER Metal2 ;
      RECT 0.000 0.000 80.000 180.000 ;
    LAYER Metal3 ;
      RECT 0.000 0.000 80.000 178.000 ;
    LAYER Metal4 ;
      RECT 0.000 0.000 80.000 178.000 ;
    LAYER Metal5 ;
      RECT 0.000 0.000 80.000 178.000 ;
    LAYER TopMetal1 ;
      RECT 0.000 0.000 80.000 178.000 ;
    LAYER TopMetal2 ;
      RECT 0.000 0.000 80.000 132.500 ;
    LAYER Via1 ;
      RECT 0.000 0.000 80.000 180.000 ;
    LAYER Via2 ;
      RECT 0.000 0.000 80.000 180.000 ;
  END
END sg13g2_IOPadInOut16mA

MACRO sg13g2_IOPadInOut30mA
    CLASS PAD INOUT ;
    ORIGIN 0.000 0.000 ;
    FOREIGN sg13g2_IOPadInOut30mA 0.000 0.000 ;
    SIZE 80.000 BY 180.000 ;
    SYMMETRY X Y R90 ;
    SITE sg13g2_ioSite ;
  PIN c2p
    DIRECTION INPUT ;
    USE SIGNAL ;
    PORT
      LAYER Metal2 ;
        RECT 18.330 178.090 18.620 180.000 ;
      LAYER Metal3 ;
        RECT 18.225 179.710 18.725 180.000 ;
    END
  END c2p
  PIN c2p_en
    DIRECTION INPUT ;
    USE SIGNAL ;
    PORT
      LAYER Metal2 ;
        RECT 21.380 174.045 21.670 180.000 ;
      LAYER Metal3 ;
        RECT 21.275 179.710 21.775 180.000 ;
    END
  END c2p_en
  PIN iovdd
    DIRECTION INOUT ;
    USE POWER ;
    PORT
      LAYER Metal3 ;
        RECT 0.000 93.500 80.000 119.000 ;
    END
    PORT
      LAYER Metal3 ;
        RECT 0.000 66.000 80.000 91.500 ;
    END
    PORT
      LAYER Metal4 ;
        RECT 0.000 93.500 80.000 119.000 ;
    END
    PORT
      LAYER Metal4 ;
        RECT 0.000 66.000 80.000 91.500 ;
    END
    PORT
      LAYER Metal5 ;
        RECT 0.000 93.500 80.000 119.000 ;
    END
    PORT
      LAYER Metal5 ;
        RECT 0.000 66.000 80.000 91.500 ;
    END
    PORT
      LAYER TopMetal1 ;
        RECT 0.000 93.500 80.000 119.000 ;
    END
    PORT
      LAYER TopMetal1 ;
        RECT 0.000 66.000 80.000 91.500 ;
    END
    PORT
      LAYER TopMetal2 ;
        RECT 0.000 95.000 80.000 117.500 ;
    END
    PORT
      LAYER TopMetal2 ;
        RECT 0.000 67.500 80.000 90.000 ;
    END
  END iovdd
  PIN iovss
    DIRECTION INOUT ;
    USE GROUND ;
    PORT
      LAYER Metal3 ;
        RECT 0.000 7.000 80.000 32.500 ;
    END
    PORT
      LAYER Metal3 ;
        RECT 0.000 126.000 80.000 134.000 ;
    END
    PORT
      LAYER Metal3 ;
        RECT 0.000 34.500 80.000 60.000 ;
    END
    PORT
      LAYER Metal4 ;
        RECT 0.000 7.000 80.000 32.500 ;
    END
    PORT
      LAYER Metal4 ;
        RECT 0.000 126.000 80.000 134.000 ;
    END
    PORT
      LAYER Metal4 ;
        RECT 0.000 34.500 80.000 60.000 ;
    END
    PORT
      LAYER Metal5 ;
        RECT 0.000 7.000 80.000 32.500 ;
    END
    PORT
      LAYER Metal5 ;
        RECT 0.000 126.000 80.000 134.000 ;
    END
    PORT
      LAYER Metal5 ;
        RECT 0.000 34.500 80.000 60.000 ;
    END
    PORT
      LAYER TopMetal1 ;
        RECT 0.000 7.000 80.000 32.500 ;
    END
    PORT
      LAYER TopMetal1 ;
        RECT 0.000 126.000 80.000 134.000 ;
    END
    PORT
      LAYER TopMetal1 ;
        RECT 0.000 34.500 80.000 60.000 ;
    END
    PORT
      LAYER TopMetal2 ;
        RECT 0.000 36.000 80.000 58.500 ;
    END
    PORT
      LAYER TopMetal2 ;
        RECT 0.000 8.500 80.000 31.000 ;
    END
    PORT
      LAYER TopMetal2 ;
        RECT 0.000 127.500 80.000 132.500 ;
    END
  END iovss
  PIN p2c
    DIRECTION OUTPUT ;
    USE SIGNAL ;
    PORT
      LAYER Metal2 ;
        RECT 59.830 157.810 60.120 180.000 ;
      LAYER Metal3 ;
        RECT 59.725 179.710 60.225 180.000 ;
    END
  END p2c
  PIN pad
    DIRECTION INOUT ;
    USE SIGNAL ;
    PORT
      LAYER Metal2 ;
        RECT 5.000 0.000 75.000 3.000 ;
      LAYER Metal3 ;
        RECT 5.000 0.000 75.000 3.000 ;
      LAYER Metal4 ;
        RECT 5.000 0.000 75.000 3.000 ;
      LAYER Metal5 ;
        RECT 5.000 0.000 75.000 3.000 ;
      LAYER TopMetal1 ;
        RECT 5.000 0.000 75.000 3.000 ;
      LAYER TopMetal2 ;
        RECT 5.000 0.000 75.000 3.000 ;
    END
  END pad
  PIN vdd
    DIRECTION INOUT ;
    USE POWER ;
    PORT
      LAYER Metal3 ;
        RECT 0.000 160.000 80.000 178.000 ;
    END
    PORT
      LAYER Metal4 ;
        RECT 0.000 140.000 80.000 155.800 ;
    END
    PORT
      LAYER Metal5 ;
        RECT 0.000 140.000 80.000 158.000 ;
    END
    PORT
      LAYER TopMetal1 ;
        RECT 0.000 140.000 80.000 158.000 ;
    END
  END vdd
  PIN vss
    DIRECTION INOUT ;
    USE GROUND ;
    PORT
      LAYER Metal3 ;
        RECT 0.000 140.000 80.000 158.000 ;
    END
    PORT
      LAYER Metal4 ;
        RECT 0.000 162.200 80.000 178.000 ;
    END
    PORT
      LAYER Metal5 ;
        RECT 0.000 160.000 80.000 178.000 ;
    END
    PORT
      LAYER TopMetal1 ;
        RECT 0.000 160.000 80.000 178.000 ;
    END
  END vss
  OBS
    LAYER Metal1 ;
      RECT 0.000 0.000 80.000 180.000 ;
    LAYER Metal2 ;
      RECT 0.000 0.000 80.000 180.000 ;
    LAYER Metal3 ;
      RECT 0.000 0.000 80.000 178.000 ;
    LAYER Metal4 ;
      RECT 0.000 0.000 80.000 178.000 ;
    LAYER Metal5 ;
      RECT 0.000 0.000 80.000 178.000 ;
    LAYER TopMetal1 ;
      RECT 0.000 0.000 80.000 178.000 ;
    LAYER TopMetal2 ;
      RECT 0.000 0.000 80.000 132.500 ;
    LAYER Via1 ;
      RECT 0.000 0.000 80.000 180.000 ;
    LAYER Via2 ;
      RECT 0.000 0.000 80.000 180.000 ;
  END
END sg13g2_IOPadInOut30mA

MACRO sg13g2_IOPadAnalog
    CLASS PAD INOUT ;
    ORIGIN 0.000 0.000 ;
    FOREIGN sg13g2_IOPadAnalog 0.000 0.000 ;
    SIZE 80.000 BY 180.000 ;
    SYMMETRY X Y R90 ;
    SITE sg13g2_ioSite ;
  PIN iovdd
    DIRECTION INOUT ;
    USE POWER ;
    PORT
      LAYER Metal3 ;
        RECT 0.000 93.500 80.000 119.000 ;
    END
    PORT
      LAYER Metal3 ;
        RECT 0.000 66.000 80.000 91.500 ;
    END
    PORT
      LAYER Metal4 ;
        RECT 0.000 93.500 80.000 119.000 ;
    END
    PORT
      LAYER Metal4 ;
        RECT 0.000 66.000 80.000 91.500 ;
    END
    PORT
      LAYER Metal5 ;
        RECT 0.000 93.500 80.000 119.000 ;
    END
    PORT
      LAYER Metal5 ;
        RECT 0.000 66.000 80.000 91.500 ;
    END
    PORT
      LAYER TopMetal1 ;
        RECT 0.000 93.500 80.000 119.000 ;
    END
    PORT
      LAYER TopMetal1 ;
        RECT 0.000 66.000 80.000 91.500 ;
    END
    PORT
      LAYER TopMetal2 ;
        RECT 0.000 95.000 80.000 117.500 ;
    END
    PORT
      LAYER TopMetal2 ;
        RECT 0.000 67.500 80.000 90.000 ;
    END
  END iovdd
  PIN iovss
    DIRECTION INOUT ;
    USE GROUND ;
    PORT
      LAYER Metal3 ;
        RECT 0.000 7.000 80.000 32.500 ;
    END
    PORT
      LAYER Metal3 ;
        RECT 0.000 126.000 80.000 134.000 ;
    END
    PORT
      LAYER Metal3 ;
        RECT 0.000 34.500 80.000 60.000 ;
    END
    PORT
      LAYER Metal4 ;
        RECT 0.000 7.000 80.000 32.500 ;
    END
    PORT
      LAYER Metal4 ;
        RECT 0.000 126.000 80.000 134.000 ;
    END
    PORT
      LAYER Metal4 ;
        RECT 0.000 34.500 80.000 60.000 ;
    END
    PORT
      LAYER Metal5 ;
        RECT 0.000 7.000 80.000 32.500 ;
    END
    PORT
      LAYER Metal5 ;
        RECT 0.000 126.000 80.000 134.000 ;
    END
    PORT
      LAYER Metal5 ;
        RECT 0.000 34.500 80.000 60.000 ;
    END
    PORT
      LAYER TopMetal1 ;
        RECT 0.000 7.000 80.000 32.500 ;
    END
    PORT
      LAYER TopMetal1 ;
        RECT 0.000 126.000 80.000 134.000 ;
    END
    PORT
      LAYER TopMetal1 ;
        RECT 0.000 34.500 80.000 60.000 ;
    END
    PORT
      LAYER TopMetal2 ;
        RECT 0.000 36.000 80.000 58.500 ;
    END
    PORT
      LAYER TopMetal2 ;
        RECT 0.000 8.500 80.000 31.000 ;
    END
    PORT
      LAYER TopMetal2 ;
        RECT 0.000 127.500 80.000 132.500 ;
    END
  END iovss
  PIN pad
    DIRECTION INOUT ;
    USE SIGNAL ;
    PORT
      LAYER Metal2 ;
        RECT 26.105 179.000 50.875 180.000 ;
      LAYER Metal3 ;
        RECT 26.105 179.710 50.875 180.000 ;
    END
    PORT
      LAYER Metal2 ;
        RECT 5.000 0.000 75.000 3.000 ;
      LAYER Metal3 ;
        RECT 5.000 0.000 75.000 3.000 ;
      LAYER Metal4 ;
        RECT 5.000 0.000 75.000 3.000 ;
      LAYER Metal5 ;
        RECT 5.000 0.000 75.000 3.000 ;
      LAYER TopMetal1 ;
        RECT 5.000 0.000 75.000 3.000 ;
      LAYER TopMetal2 ;
        RECT 5.000 0.000 75.000 3.000 ;
    END
  END pad
  PIN padres
    DIRECTION INOUT ;
    USE SIGNAL ;
    PORT
      LAYER Metal2 ;
        RECT 57.460 147.180 57.750 180.000 ;
      LAYER Metal3 ;
        RECT 57.355 179.710 57.855 180.000 ;
    END
  END padres
  PIN vdd
    DIRECTION INOUT ;
    USE POWER ;
    PORT
      LAYER Metal3 ;
        RECT 0.000 160.000 80.000 178.000 ;
    END
    PORT
      LAYER Metal4 ;
        RECT 0.000 140.000 80.000 155.800 ;
    END
    PORT
      LAYER Metal5 ;
        RECT 0.000 140.000 80.000 158.000 ;
    END
    PORT
      LAYER TopMetal1 ;
        RECT 0.000 140.000 80.000 158.000 ;
    END
  END vdd
  PIN vss
    DIRECTION INOUT ;
    USE GROUND ;
    PORT
      LAYER Metal3 ;
        RECT 0.000 140.000 80.000 158.000 ;
    END
    PORT
      LAYER Metal4 ;
        RECT 0.000 162.200 80.000 178.000 ;
    END
    PORT
      LAYER Metal5 ;
        RECT 0.000 160.000 80.000 178.000 ;
    END
    PORT
      LAYER TopMetal1 ;
        RECT 0.000 160.000 80.000 178.000 ;
    END
  END vss
  OBS
    LAYER Metal1 ;
      RECT 0.000 0.000 80.000 180.000 ;
    LAYER Metal2 ;
      RECT 0.000 0.000 80.000 180.000 ;
    LAYER Metal3 ;
      RECT 0.000 0.000 80.000 178.000 ;
    LAYER Metal4 ;
      RECT 0.000 0.000 80.000 178.000 ;
    LAYER Metal5 ;
      RECT 0.000 0.000 80.000 178.000 ;
    LAYER TopMetal1 ;
      RECT 0.000 0.000 80.000 178.000 ;
    LAYER TopMetal2 ;
      RECT 0.000 0.000 80.000 132.500 ;
    LAYER Via1 ;
      RECT 0.000 0.000 80.000 180.000 ;
    LAYER Via2 ;
      RECT 0.000 0.000 80.000 180.000 ;
  END
END sg13g2_IOPadAnalog

MACRO sg13g2_IOPadIOVss
    CLASS PAD POWER ;
    ORIGIN 0.000 0.000 ;
    FOREIGN sg13g2_IOPadIOVss 0.000 0.000 ;
    SIZE 80.000 BY 180.000 ;
    SYMMETRY X Y R90 ;
    SITE sg13g2_ioSite ;
  PIN iovdd
    DIRECTION INOUT ;
    USE POWER ;
    PORT
      LAYER Metal3 ;
        RECT 0.000 93.500 80.000 119.000 ;
    END
    PORT
      LAYER Metal3 ;
        RECT 0.000 66.000 80.000 91.500 ;
    END
    PORT
      LAYER Metal4 ;
        RECT 0.000 93.500 80.000 119.000 ;
    END
    PORT
      LAYER Metal4 ;
        RECT 0.000 66.000 80.000 91.500 ;
    END
    PORT
      LAYER Metal5 ;
        RECT 0.000 93.500 80.000 119.000 ;
    END
    PORT
      LAYER Metal5 ;
        RECT 0.000 66.000 80.000 91.500 ;
    END
    PORT
      LAYER TopMetal1 ;
        RECT 0.000 93.500 80.000 119.000 ;
    END
    PORT
      LAYER TopMetal1 ;
        RECT 0.000 66.000 80.000 91.500 ;
    END
    PORT
      LAYER TopMetal2 ;
        RECT 0.000 95.000 80.000 117.500 ;
    END
    PORT
      LAYER TopMetal2 ;
        RECT 0.000 67.500 80.000 90.000 ;
    END
  END iovdd
  PIN iovss
    DIRECTION INOUT ;
    USE GROUND ;
    PORT
      LAYER Metal2 ;
        RECT 5.000 0.000 75.000 3.000 ;
      LAYER Metal3 ;
        RECT 5.000 0.000 75.000 3.000 ;
      LAYER Metal4 ;
        RECT 5.000 0.000 75.000 3.000 ;
      LAYER Metal5 ;
        RECT 5.000 0.000 75.000 3.000 ;
      LAYER TopMetal1 ;
        RECT 5.000 0.000 75.000 3.000 ;
      LAYER TopMetal2 ;
        RECT 5.000 0.000 75.000 3.000 ;
    END
    PORT
      LAYER Metal3 ;
        RECT 0.000 7.000 80.000 32.500 ;
    END
    PORT
      LAYER Metal3 ;
        RECT 0.000 126.000 80.000 134.000 ;
    END
    PORT
      LAYER Metal3 ;
        RECT 0.000 34.500 80.000 60.000 ;
    END
    PORT
      LAYER Metal4 ;
        RECT 0.000 7.000 80.000 32.500 ;
    END
    PORT
      LAYER Metal4 ;
        RECT 0.000 126.000 80.000 134.000 ;
    END
    PORT
      LAYER Metal4 ;
        RECT 0.000 34.500 80.000 60.000 ;
    END
    PORT
      LAYER Metal5 ;
        RECT 0.000 7.000 80.000 32.500 ;
    END
    PORT
      LAYER Metal5 ;
        RECT 0.000 126.000 80.000 134.000 ;
    END
    PORT
      LAYER Metal5 ;
        RECT 0.000 34.500 80.000 60.000 ;
    END
    PORT
      LAYER TopMetal1 ;
        RECT 0.000 7.000 80.000 32.500 ;
    END
    PORT
      LAYER TopMetal1 ;
        RECT 0.000 126.000 80.000 134.000 ;
    END
    PORT
      LAYER TopMetal1 ;
        RECT 0.000 34.500 80.000 60.000 ;
    END
    PORT
      LAYER TopMetal2 ;
        RECT 0.000 36.000 80.000 58.500 ;
    END
    PORT
      LAYER TopMetal2 ;
        RECT 0.000 8.500 80.000 31.000 ;
    END
    PORT
      LAYER TopMetal2 ;
        RECT 0.000 127.500 80.000 132.500 ;
    END
  END iovss
  PIN vdd
    DIRECTION INOUT ;
    USE POWER ;
    PORT
      LAYER Metal3 ;
        RECT 0.000 160.000 80.000 178.000 ;
    END
    PORT
      LAYER Metal4 ;
        RECT 0.000 140.000 80.000 155.800 ;
    END
    PORT
      LAYER Metal5 ;
        RECT 0.000 140.000 80.000 158.000 ;
    END
    PORT
      LAYER TopMetal1 ;
        RECT 0.000 140.000 80.000 158.000 ;
    END
  END vdd
  PIN vss
    DIRECTION INOUT ;
    USE GROUND ;
    PORT
      LAYER Metal3 ;
        RECT 0.000 140.000 80.000 158.000 ;
    END
    PORT
      LAYER Metal4 ;
        RECT 0.000 162.200 80.000 178.000 ;
    END
    PORT
      LAYER Metal5 ;
        RECT 0.000 160.000 80.000 178.000 ;
    END
    PORT
      LAYER TopMetal1 ;
        RECT 0.000 160.000 80.000 178.000 ;
    END
  END vss
  OBS
    LAYER Metal1 ;
      RECT 0.000 0.000 80.000 180.000 ;
    LAYER Metal2 ;
      RECT 0.000 0.000 80.000 180.000 ;
    LAYER Metal3 ;
      RECT 0.000 0.000 80.000 178.000 ;
    LAYER Metal4 ;
      RECT 0.000 0.000 80.000 178.000 ;
    LAYER Metal5 ;
      RECT 0.000 0.000 80.000 178.000 ;
    LAYER TopMetal1 ;
      RECT 0.000 0.000 80.000 178.000 ;
    LAYER TopMetal2 ;
      RECT 0.000 0.000 80.000 132.500 ;
    LAYER Via1 ;
      RECT 0.000 0.000 80.000 180.000 ;
    LAYER Via2 ;
      RECT 0.000 0.000 80.000 180.000 ;
  END
END sg13g2_IOPadIOVss

MACRO sg13g2_IOPadIOVdd
    CLASS PAD POWER ;
    ORIGIN 0.000 0.000 ;
    FOREIGN sg13g2_IOPadIOVdd 0.000 0.000 ;
    SIZE 80.000 BY 180.000 ;
    SYMMETRY X Y R90 ;
    SITE sg13g2_ioSite ;
  PIN iovdd
    DIRECTION INOUT ;
    USE POWER ;
    PORT
      LAYER Metal2 ;
        RECT 5.000 0.000 75.000 3.000 ;
      LAYER Metal3 ;
        RECT 5.000 0.000 75.000 3.000 ;
      LAYER Metal4 ;
        RECT 5.000 0.000 75.000 3.000 ;
      LAYER Metal5 ;
        RECT 5.000 0.000 75.000 3.000 ;
      LAYER TopMetal1 ;
        RECT 5.000 0.000 75.000 3.000 ;
      LAYER TopMetal2 ;
        RECT 5.000 0.000 75.000 3.000 ;
    END
    PORT
      LAYER Metal3 ;
        RECT 0.000 93.500 80.000 119.000 ;
    END
    PORT
      LAYER Metal3 ;
        RECT 0.000 66.000 80.000 91.500 ;
    END
    PORT
      LAYER Metal4 ;
        RECT 0.000 93.500 80.000 119.000 ;
    END
    PORT
      LAYER Metal4 ;
        RECT 0.000 66.000 80.000 91.500 ;
    END
    PORT
      LAYER Metal5 ;
        RECT 0.000 93.500 80.000 119.000 ;
    END
    PORT
      LAYER Metal5 ;
        RECT 0.000 66.000 80.000 91.500 ;
    END
    PORT
      LAYER TopMetal1 ;
        RECT 0.000 93.500 80.000 119.000 ;
    END
    PORT
      LAYER TopMetal1 ;
        RECT 0.000 66.000 80.000 91.500 ;
    END
    PORT
      LAYER TopMetal2 ;
        RECT 0.000 95.000 80.000 117.500 ;
    END
    PORT
      LAYER TopMetal2 ;
        RECT 0.000 67.500 80.000 90.000 ;
    END
  END iovdd
  PIN iovss
    DIRECTION INOUT ;
    USE GROUND ;
    PORT
      LAYER Metal3 ;
        RECT 0.000 7.000 80.000 32.500 ;
    END
    PORT
      LAYER Metal3 ;
        RECT 0.000 126.000 80.000 134.000 ;
    END
    PORT
      LAYER Metal3 ;
        RECT 0.000 34.500 80.000 60.000 ;
    END
    PORT
      LAYER Metal4 ;
        RECT 0.000 7.000 80.000 32.500 ;
    END
    PORT
      LAYER Metal4 ;
        RECT 0.000 126.000 80.000 134.000 ;
    END
    PORT
      LAYER Metal4 ;
        RECT 0.000 34.500 80.000 60.000 ;
    END
    PORT
      LAYER Metal5 ;
        RECT 0.000 7.000 80.000 32.500 ;
    END
    PORT
      LAYER Metal5 ;
        RECT 0.000 126.000 80.000 134.000 ;
    END
    PORT
      LAYER Metal5 ;
        RECT 0.000 34.500 80.000 60.000 ;
    END
    PORT
      LAYER TopMetal1 ;
        RECT 0.000 7.000 80.000 32.500 ;
    END
    PORT
      LAYER TopMetal1 ;
        RECT 0.000 126.000 80.000 134.000 ;
    END
    PORT
      LAYER TopMetal1 ;
        RECT 0.000 34.500 80.000 60.000 ;
    END
    PORT
      LAYER TopMetal2 ;
        RECT 0.000 36.000 3.900 58.500 ;
    END
    PORT
      LAYER TopMetal2 ;
        RECT 0.000 8.500 3.900 31.000 ;
    END
    PORT
      LAYER TopMetal2 ;
        RECT 76.100 36.000 80.000 58.500 ;
    END
    PORT
      LAYER TopMetal2 ;
        RECT 0.000 127.500 80.000 132.500 ;
    END
    PORT
      LAYER TopMetal2 ;
        RECT 76.100 8.500 80.000 31.000 ;
    END
  END iovss
  PIN vdd
    DIRECTION INOUT ;
    USE POWER ;
    PORT
      LAYER Metal3 ;
        RECT 0.000 160.000 80.000 178.000 ;
    END
    PORT
      LAYER Metal4 ;
        RECT 0.000 140.000 80.000 155.800 ;
    END
    PORT
      LAYER Metal5 ;
        RECT 0.000 140.000 80.000 158.000 ;
    END
    PORT
      LAYER TopMetal1 ;
        RECT 0.000 140.000 80.000 158.000 ;
    END
  END vdd
  PIN vss
    DIRECTION INOUT ;
    USE GROUND ;
    PORT
      LAYER Metal3 ;
        RECT 0.000 140.000 80.000 158.000 ;
    END
    PORT
      LAYER Metal4 ;
        RECT 0.000 162.200 80.000 178.000 ;
    END
    PORT
      LAYER Metal5 ;
        RECT 0.000 160.000 80.000 178.000 ;
    END
    PORT
      LAYER TopMetal1 ;
        RECT 0.000 160.000 80.000 178.000 ;
    END
  END vss
  OBS
    LAYER Metal1 ;
      RECT 0.000 0.000 80.000 180.000 ;
    LAYER Metal2 ;
      RECT 0.000 0.000 80.000 180.000 ;
    LAYER Metal3 ;
      RECT 0.000 0.000 80.000 178.000 ;
    LAYER Metal4 ;
      RECT 0.000 0.000 80.000 178.000 ;
    LAYER Metal5 ;
      RECT 0.000 0.000 80.000 178.000 ;
    LAYER TopMetal1 ;
      RECT 0.000 0.000 80.000 178.000 ;
    LAYER TopMetal2 ;
      RECT 0.000 0.000 80.000 132.500 ;
    LAYER Via1 ;
      RECT 0.000 0.000 80.000 180.000 ;
    LAYER Via2 ;
      RECT 0.000 0.000 80.000 180.000 ;
  END
END sg13g2_IOPadIOVdd

MACRO sg13g2_IOPadVss
    CLASS PAD POWER ;
    ORIGIN 0.000 0.000 ;
    FOREIGN sg13g2_IOPadVss 0.000 0.000 ;
    SIZE 80.000 BY 180.000 ;
    SYMMETRY X Y R90 ;
    SITE sg13g2_ioSite ;
  PIN iovdd
    DIRECTION INOUT ;
    USE POWER ;
    PORT
      LAYER Metal3 ;
        RECT 0.000 93.500 80.000 119.000 ;
    END
    PORT
      LAYER Metal3 ;
        RECT 0.000 66.000 80.000 91.500 ;
    END
    PORT
      LAYER Metal4 ;
        RECT 0.000 93.500 80.000 119.000 ;
    END
    PORT
      LAYER Metal4 ;
        RECT 0.000 66.000 80.000 91.500 ;
    END
    PORT
      LAYER Metal5 ;
        RECT 0.000 93.500 80.000 119.000 ;
    END
    PORT
      LAYER Metal5 ;
        RECT 0.000 66.000 80.000 91.500 ;
    END
    PORT
      LAYER TopMetal1 ;
        RECT 0.000 93.500 80.000 119.000 ;
    END
    PORT
      LAYER TopMetal1 ;
        RECT 0.000 66.000 80.000 91.500 ;
    END
    PORT
      LAYER TopMetal2 ;
        RECT 0.000 95.000 80.000 117.500 ;
    END
    PORT
      LAYER TopMetal2 ;
        RECT 0.000 67.500 80.000 90.000 ;
    END
  END iovdd
  PIN iovss
    DIRECTION INOUT ;
    USE GROUND ;
    PORT
      LAYER Metal3 ;
        RECT 0.000 7.000 80.000 32.500 ;
    END
    PORT
      LAYER Metal3 ;
        RECT 0.000 126.000 80.000 134.000 ;
    END
    PORT
      LAYER Metal3 ;
        RECT 0.000 34.500 80.000 60.000 ;
    END
    PORT
      LAYER Metal4 ;
        RECT 0.000 7.000 80.000 32.500 ;
    END
    PORT
      LAYER Metal4 ;
        RECT 0.000 126.000 80.000 134.000 ;
    END
    PORT
      LAYER Metal4 ;
        RECT 0.000 34.500 80.000 60.000 ;
    END
    PORT
      LAYER Metal5 ;
        RECT 0.000 7.000 80.000 32.500 ;
    END
    PORT
      LAYER Metal5 ;
        RECT 0.000 126.000 80.000 134.000 ;
    END
    PORT
      LAYER Metal5 ;
        RECT 0.000 34.500 80.000 60.000 ;
    END
    PORT
      LAYER TopMetal1 ;
        RECT 0.000 7.000 80.000 32.500 ;
    END
    PORT
      LAYER TopMetal1 ;
        RECT 0.000 126.000 80.000 134.000 ;
    END
    PORT
      LAYER TopMetal1 ;
        RECT 0.000 34.500 80.000 60.000 ;
    END
    PORT
      LAYER TopMetal2 ;
        RECT 0.000 36.000 80.000 58.500 ;
    END
    PORT
      LAYER TopMetal2 ;
        RECT 0.000 8.500 80.000 31.000 ;
    END
    PORT
      LAYER TopMetal2 ;
        RECT 0.000 127.500 80.000 132.500 ;
    END
  END iovss
  PIN vdd
    DIRECTION INOUT ;
    USE POWER ;
    PORT
      LAYER Metal3 ;
        RECT 0.000 160.000 80.000 178.000 ;
    END
    PORT
      LAYER Metal4 ;
        RECT 0.000 140.000 80.000 155.800 ;
    END
    PORT
      LAYER Metal5 ;
        RECT 0.000 140.000 80.000 158.000 ;
    END
    PORT
      LAYER TopMetal1 ;
        RECT 0.000 140.000 80.000 158.000 ;
    END
  END vdd
  PIN vss
    DIRECTION INOUT ;
    USE GROUND ;
    PORT
      LAYER Metal2 ;
        RECT 5.000 0.000 75.000 3.000 ;
      LAYER Metal3 ;
        RECT 5.000 0.000 75.000 3.000 ;
      LAYER Metal4 ;
        RECT 5.000 0.000 75.000 3.000 ;
      LAYER Metal5 ;
        RECT 5.000 0.000 75.000 3.000 ;
      LAYER TopMetal1 ;
        RECT 5.000 0.000 75.000 3.000 ;
      LAYER TopMetal2 ;
        RECT 5.000 0.000 75.000 3.000 ;
    END
    PORT
      LAYER Metal3 ;
        RECT 0.000 140.000 80.000 158.000 ;
    END
    PORT
      LAYER Metal4 ;
        RECT 0.000 162.200 80.000 178.000 ;
    END
    PORT
      LAYER Metal5 ;
        RECT 0.000 160.000 80.000 178.000 ;
    END
    PORT
      LAYER TopMetal1 ;
        RECT 0.000 160.000 80.000 178.000 ;
    END
  END vss
  OBS
    LAYER Metal1 ;
      RECT 0.000 0.000 80.000 180.000 ;
    LAYER Metal2 ;
      RECT 0.000 0.000 80.000 180.000 ;
    LAYER Metal3 ;
      RECT 0.000 0.000 80.000 178.000 ;
    LAYER Metal4 ;
      RECT 0.000 0.000 80.000 178.000 ;
    LAYER Metal5 ;
      RECT 0.000 0.000 80.000 178.000 ;
    LAYER TopMetal1 ;
      RECT 0.000 0.000 80.000 178.000 ;
    LAYER TopMetal2 ;
      RECT 0.000 0.000 80.000 132.500 ;
    LAYER Via1 ;
      RECT 0.000 0.000 80.000 180.000 ;
    LAYER Via2 ;
      RECT 0.000 0.000 80.000 180.000 ;
  END
END sg13g2_IOPadVss

MACRO sg13g2_IOPadVdd
    CLASS PAD POWER ;
    ORIGIN 0.000 0.000 ;
    FOREIGN sg13g2_IOPadVdd 0.000 0.000 ;
    SIZE 80.000 BY 180.000 ;
    SYMMETRY X Y R90 ;
    SITE sg13g2_ioSite ;
  PIN iovdd
    DIRECTION INOUT ;
    USE POWER ;
    PORT
      LAYER Metal3 ;
        RECT 0.000 93.500 80.000 119.000 ;
    END
    PORT
      LAYER Metal3 ;
        RECT 0.000 66.000 80.000 91.500 ;
    END
    PORT
      LAYER Metal4 ;
        RECT 0.000 93.500 80.000 119.000 ;
    END
    PORT
      LAYER Metal4 ;
        RECT 0.000 66.000 80.000 91.500 ;
    END
    PORT
      LAYER Metal5 ;
        RECT 0.000 93.500 80.000 119.000 ;
    END
    PORT
      LAYER Metal5 ;
        RECT 0.000 66.000 80.000 91.500 ;
    END
    PORT
      LAYER TopMetal1 ;
        RECT 0.000 93.500 80.000 119.000 ;
    END
    PORT
      LAYER TopMetal1 ;
        RECT 0.000 66.000 80.000 91.500 ;
    END
    PORT
      LAYER TopMetal2 ;
        RECT 76.100 67.500 80.000 90.000 ;
    END
    PORT
      LAYER TopMetal2 ;
        RECT 76.100 95.000 80.000 117.500 ;
    END
    PORT
      LAYER TopMetal2 ;
        RECT 0.000 95.000 3.900 117.500 ;
    END
    PORT
      LAYER TopMetal2 ;
        RECT 0.000 67.500 3.900 90.000 ;
    END
  END iovdd
  PIN iovss
    DIRECTION INOUT ;
    USE GROUND ;
    PORT
      LAYER Metal3 ;
        RECT 0.000 7.000 80.000 32.500 ;
    END
    PORT
      LAYER Metal3 ;
        RECT 0.000 126.000 80.000 134.000 ;
    END
    PORT
      LAYER Metal3 ;
        RECT 0.000 34.500 80.000 60.000 ;
    END
    PORT
      LAYER Metal4 ;
        RECT 0.000 7.000 80.000 32.500 ;
    END
    PORT
      LAYER Metal4 ;
        RECT 0.000 126.000 80.000 134.000 ;
    END
    PORT
      LAYER Metal4 ;
        RECT 0.000 34.500 80.000 60.000 ;
    END
    PORT
      LAYER Metal5 ;
        RECT 0.000 7.000 80.000 32.500 ;
    END
    PORT
      LAYER Metal5 ;
        RECT 0.000 126.000 80.000 134.000 ;
    END
    PORT
      LAYER Metal5 ;
        RECT 0.000 34.500 80.000 60.000 ;
    END
    PORT
      LAYER TopMetal1 ;
        RECT 0.000 7.000 80.000 32.500 ;
    END
    PORT
      LAYER TopMetal1 ;
        RECT 0.000 126.000 80.000 134.000 ;
    END
    PORT
      LAYER TopMetal1 ;
        RECT 0.000 34.500 80.000 60.000 ;
    END
    PORT
      LAYER TopMetal2 ;
        RECT 0.000 36.000 3.900 58.500 ;
    END
    PORT
      LAYER TopMetal2 ;
        RECT 0.000 8.500 3.900 31.000 ;
    END
    PORT
      LAYER TopMetal2 ;
        RECT 76.100 127.500 80.000 132.500 ;
    END
    PORT
      LAYER TopMetal2 ;
        RECT 76.100 36.000 80.000 58.500 ;
    END
    PORT
      LAYER TopMetal2 ;
        RECT 76.100 8.500 80.000 31.000 ;
    END
    PORT
      LAYER TopMetal2 ;
        RECT 0.000 127.500 3.900 132.500 ;
    END
  END iovss
  PIN vdd
    DIRECTION INOUT ;
    USE POWER ;
    PORT
      LAYER Metal2 ;
        RECT 5.000 0.000 75.000 3.000 ;
      LAYER Metal3 ;
        RECT 5.000 0.000 75.000 3.000 ;
      LAYER Metal4 ;
        RECT 5.000 0.000 75.000 3.000 ;
      LAYER Metal5 ;
        RECT 5.000 0.000 75.000 3.000 ;
      LAYER TopMetal1 ;
        RECT 5.000 0.000 75.000 3.000 ;
      LAYER TopMetal2 ;
        RECT 5.000 0.000 75.000 3.000 ;
    END
    PORT
      LAYER Metal3 ;
        RECT 0.000 160.000 80.000 178.000 ;
    END
    PORT
      LAYER Metal4 ;
        RECT 0.000 140.000 80.000 155.800 ;
    END
    PORT
      LAYER Metal5 ;
        RECT 0.000 140.000 80.000 158.000 ;
    END
    PORT
      LAYER TopMetal1 ;
        RECT 0.000 140.000 80.000 158.000 ;
    END
    PORT
      LAYER TopMetal2 ;
        RECT 7.500 141.500 72.500 156.500 ;
    END
  END vdd
  PIN vss
    DIRECTION INOUT ;
    USE GROUND ;
    PORT
      LAYER Metal3 ;
        RECT 0.000 140.000 80.000 158.000 ;
    END
    PORT
      LAYER Metal4 ;
        RECT 0.000 162.200 80.000 178.000 ;
    END
    PORT
      LAYER Metal5 ;
        RECT 0.000 160.000 80.000 178.000 ;
    END
    PORT
      LAYER TopMetal1 ;
        RECT 0.000 160.000 80.000 178.000 ;
    END
  END vss
  OBS
    LAYER Metal1 ;
      RECT 0.000 0.000 80.000 180.000 ;
    LAYER Metal2 ;
      RECT 0.000 0.000 80.000 180.000 ;
    LAYER Metal3 ;
      RECT 0.000 0.000 80.000 178.000 ;
    LAYER Metal4 ;
      RECT 0.000 0.000 80.000 178.000 ;
    LAYER Metal5 ;
      RECT 0.000 0.000 80.000 178.000 ;
    LAYER TopMetal1 ;
      RECT 0.000 0.000 80.000 178.000 ;
    LAYER TopMetal2 ;
      RECT 0.000 0.000 80.000 156.500 ;
    LAYER Via1 ;
      RECT 0.000 0.000 80.000 180.000 ;
    LAYER Via2 ;
      RECT 0.000 0.000 80.000 180.000 ;
  END
END sg13g2_IOPadVdd
